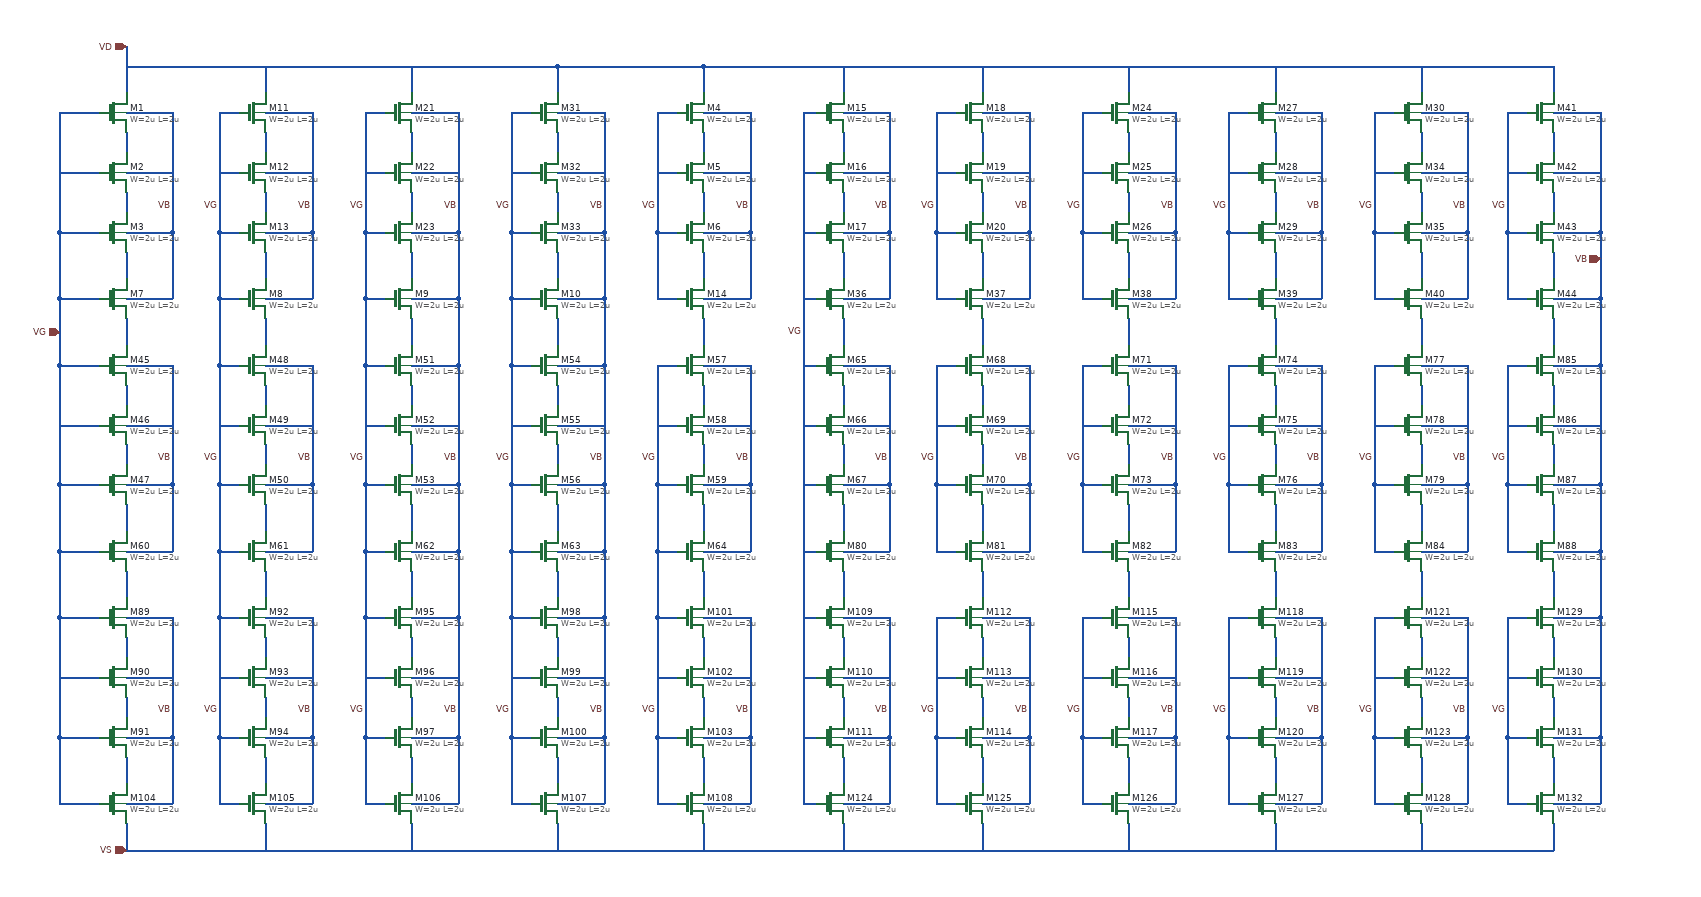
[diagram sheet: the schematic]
v {xschem version=3.4.0 file_version=1.2
}
G {}
K {}
V {}
S {}
E {}
N -420 -250 -420 -220 {
lab=#net1}
N -420 -160 -420 -130 {
lab=#net2}
N -420 -280 -350 -280 {
lab=VB}
N -420 -190 -350 -190 {
lab=VB}
N -420 -100 -350 -100 {
lab=VB}
N -520 -280 -460 -280 {
lab=#net3}
N -520 -100 -460 -100 {
lab=#net3}
N -520 -190 -460 -190 {
lab=#net3}
N -420 -380 -420 -310 {
lab=VD}
N -210 -280 -140 -280 {
lab=VB}
N -210 -190 -140 -190 {
lab=VB}
N -210 -100 -140 -100 {
lab=VB}
N 10 -280 80 -280 {
lab=VB}
N 10 -190 80 -190 {
lab=VB}
N 10 -100 80 -100 {
lab=VB}
N 230 -280 300 -280 {
lab=VB}
N 230 -190 300 -190 {
lab=VB}
N 230 -100 300 -100 {
lab=VB}
N -280 -280 -250 -280 {
lab=VG}
N -280 -100 -250 -100 {
lab=VG}
N -280 -190 -250 -190 {
lab=VG}
N -60 -280 -30 -280 {
lab=VG}
N -60 -100 -30 -100 {
lab=VG}
N -60 -190 -30 -190 {
lab=VG}
N 160 -280 190 -280 {
lab=VG}
N 160 -100 190 -100 {
lab=VG}
N 160 -190 190 -190 {
lab=VG}
N 230 -350 230 -310 {
lab=VD}
N 10 -350 10 -310 {
lab=VD}
N -210 -350 -210 -310 {
lab=VD}
N -420 -350 230 -350 {
lab=VD}
N -210 -250 -210 -220 {
lab=#net4}
N -210 -160 -210 -130 {
lab=#net5}
N 10 -250 10 -220 {
lab=#net6}
N 10 -160 10 -130 {
lab=#net7}
N 230 -250 230 -220 {
lab=#net8}
N 230 -160 230 -130 {
lab=#net9}
N -520 -280 -520 -100 {
lab=#net3}
N -350 -280 -350 -100 {
lab=VB}
N -280 -280 -280 -100 {
lab=VG}
N -140 -280 -140 -100 {
lab=VB}
N -60 -280 -60 -100 {
lab=VG}
N 80 -280 80 -100 {
lab=VB}
N 160 -280 160 -100 {
lab=VG}
N 300 -280 300 -100 {
lab=VB}
N -420 30 -420 70 {
lab=#net10}
N 230 30 230 70 {
lab=#net11}
N -210 30 -210 70 {
lab=#net12}
N 10 30 10 70 {
lab=#net13}
N 450 -280 520 -280 {
lab=VB}
N 450 -190 520 -190 {
lab=VB}
N 450 -100 520 -100 {
lab=VB}
N 380 -280 410 -280 {
lab=VG}
N 380 -100 410 -100 {
lab=VG}
N 380 -190 410 -190 {
lab=VG}
N 450 -250 450 -220 {
lab=#net14}
N 450 -160 450 -130 {
lab=#net15}
N 380 -280 380 -100 {
lab=VG}
N 520 -280 520 -100 {
lab=VB}
N 450 30 450 70 {
lab=#net16}
N 230 -350 450 -350 {
lab=VD}
N 450 -350 450 -340 {
lab=VD}
N 450 -340 450 -310 {
lab=VD}
N -420 -70 -420 -30 {
lab=#net17}
N -210 -70 -210 -30 {
lab=#net18}
N 10 -70 10 -30 {
lab=#net19}
N 230 -70 230 -30 {
lab=#net20}
N 450 -70 450 -30 {
lab=#net21}
N 380 -100 380 0 {
lab=VG}
N 380 0 410 0 {
lab=VG}
N 160 0 190 0 {
lab=VG}
N 160 -100 160 0 {
lab=VG}
N -50 0 -30 0 {
lab=VG}
N -60 0 -50 0 {
lab=VG}
N -60 -100 -60 0 {
lab=VG}
N -280 0 -250 0 {
lab=VG}
N -280 -100 -280 0 {
lab=VG}
N -520 0 -460 0 {
lab=#net3}
N -520 -100 -520 0 {
lab=#net3}
N -350 -100 -350 0 {
lab=VB}
N -420 0 -350 0 {
lab=VB}
N -140 -100 -140 0 {
lab=VB}
N -210 0 -140 0 {
lab=VB}
N 80 -100 80 0 {
lab=VB}
N 10 0 80 0 {
lab=VB}
N 300 -100 300 0 {
lab=VB}
N 230 0 300 0 {
lab=VB}
N 520 -100 520 0 {
lab=VB}
N 450 0 520 0 {
lab=VB}
N 660 -250 660 -220 {
lab=#net22}
N 660 -160 660 -130 {
lab=#net23}
N 660 -280 730 -280 {
lab=VB}
N 660 -190 730 -190 {
lab=VB}
N 660 -100 730 -100 {
lab=VB}
N 870 -280 940 -280 {
lab=VB}
N 870 -190 940 -190 {
lab=VB}
N 870 -100 940 -100 {
lab=VB}
N 1090 -280 1160 -280 {
lab=VB}
N 1090 -190 1160 -190 {
lab=VB}
N 1090 -100 1160 -100 {
lab=VB}
N 1310 -280 1380 -280 {
lab=VB}
N 1310 -190 1380 -190 {
lab=VB}
N 1310 -100 1380 -100 {
lab=VB}
N 800 -280 830 -280 {
lab=VG}
N 800 -100 830 -100 {
lab=VG}
N 800 -190 830 -190 {
lab=VG}
N 1020 -280 1050 -280 {
lab=VG}
N 1020 -100 1050 -100 {
lab=VG}
N 1020 -190 1050 -190 {
lab=VG}
N 1240 -280 1270 -280 {
lab=VG}
N 1240 -100 1270 -100 {
lab=VG}
N 1240 -190 1270 -190 {
lab=VG}
N 870 -250 870 -220 {
lab=#net24}
N 870 -160 870 -130 {
lab=#net25}
N 1090 -250 1090 -220 {
lab=#net26}
N 1090 -160 1090 -130 {
lab=#net27}
N 1310 -250 1310 -220 {
lab=#net28}
N 1310 -160 1310 -130 {
lab=#net29}
N 730 -280 730 -100 {
lab=VB}
N 800 -280 800 -100 {
lab=VG}
N 940 -280 940 -100 {
lab=VB}
N 1020 -280 1020 -100 {
lab=VG}
N 1160 -280 1160 -100 {
lab=VB}
N 1240 -280 1240 -100 {
lab=VG}
N 1380 -280 1380 -100 {
lab=VB}
N 660 30 660 70 {
lab=#net30}
N 1310 30 1310 70 {
lab=#net31}
N 870 30 870 70 {
lab=#net32}
N 1090 30 1090 70 {
lab=#net33}
N 1530 -280 1600 -280 {
lab=VB}
N 1530 -190 1600 -190 {
lab=VB}
N 1530 -100 1600 -100 {
lab=VB}
N 1460 -280 1490 -280 {
lab=VG}
N 1460 -100 1490 -100 {
lab=VG}
N 1460 -190 1490 -190 {
lab=VG}
N 1530 -250 1530 -220 {
lab=#net34}
N 1530 -160 1530 -130 {
lab=#net35}
N 1460 -280 1460 -100 {
lab=VG}
N 1600 -280 1600 -100 {
lab=VB}
N 1530 30 1530 70 {
lab=#net36}
N 660 -70 660 -30 {
lab=#net37}
N 870 -70 870 -30 {
lab=#net38}
N 1090 -70 1090 -30 {
lab=#net39}
N 1310 -70 1310 -30 {
lab=#net40}
N 1530 -70 1530 -30 {
lab=#net41}
N 1460 -100 1460 0 {
lab=VG}
N 1460 0 1490 0 {
lab=VG}
N 1240 0 1270 0 {
lab=VG}
N 1240 -100 1240 0 {
lab=VG}
N 1030 0 1050 0 {
lab=VG}
N 1020 0 1030 0 {
lab=VG}
N 1020 -100 1020 0 {
lab=VG}
N 800 0 830 0 {
lab=VG}
N 800 -100 800 0 {
lab=VG}
N 730 -100 730 0 {
lab=VB}
N 660 0 730 0 {
lab=VB}
N 940 -100 940 0 {
lab=VB}
N 870 0 940 0 {
lab=VB}
N 1160 -100 1160 0 {
lab=VB}
N 1090 0 1160 0 {
lab=VB}
N 1380 -100 1380 0 {
lab=VB}
N 1310 0 1380 0 {
lab=VB}
N 1600 -100 1600 0 {
lab=VB}
N 1530 0 1600 0 {
lab=VB}
N 1730 -280 1800 -280 {
lab=VB}
N 1730 -190 1800 -190 {
lab=VB}
N 1730 -100 1800 -100 {
lab=VB}
N 1660 -280 1690 -280 {
lab=VG}
N 1660 -100 1690 -100 {
lab=VG}
N 1660 -190 1690 -190 {
lab=VG}
N 1730 -250 1730 -220 {
lab=#net42}
N 1730 -160 1730 -130 {
lab=#net43}
N 1660 -280 1660 -100 {
lab=VG}
N 1800 -280 1800 -100 {
lab=VB}
N 1730 30 1730 70 {
lab=#net44}
N 1730 -70 1730 -30 {
lab=#net45}
N 1660 -100 1660 0 {
lab=VG}
N 1660 0 1690 0 {
lab=VG}
N 1800 -100 1800 0 {
lab=VB}
N 1730 0 1800 0 {
lab=VB}
N 450 -350 1730 -350 {
lab=VD}
N 1730 -350 1730 -310 {
lab=VD}
N 660 -350 660 -310 {
lab=VD}
N 870 -350 870 -310 {
lab=VD}
N 1090 -350 1090 -310 {
lab=VD}
N 1310 -350 1310 -310 {
lab=VD}
N 1530 -350 1530 -310 {
lab=VD}
N -420 130 -420 160 {
lab=#net1}
N -420 220 -420 250 {
lab=#net2}
N -420 100 -350 100 {
lab=VB}
N -420 190 -350 190 {
lab=VB}
N -420 280 -350 280 {
lab=VB}
N -520 100 -460 100 {
lab=#net3}
N -520 280 -460 280 {
lab=#net3}
N -520 190 -460 190 {
lab=#net3}
N -210 100 -140 100 {
lab=VB}
N -210 190 -140 190 {
lab=VB}
N -210 280 -140 280 {
lab=VB}
N 10 100 80 100 {
lab=VB}
N 10 190 80 190 {
lab=VB}
N 10 280 80 280 {
lab=VB}
N 230 100 300 100 {
lab=VB}
N 230 190 300 190 {
lab=VB}
N 230 280 300 280 {
lab=VB}
N -280 100 -250 100 {
lab=VG}
N -280 280 -250 280 {
lab=VG}
N -280 190 -250 190 {
lab=VG}
N -60 100 -30 100 {
lab=VG}
N -60 280 -30 280 {
lab=VG}
N -60 190 -30 190 {
lab=VG}
N 160 100 190 100 {
lab=VG}
N 160 280 190 280 {
lab=VG}
N 160 190 190 190 {
lab=VG}
N -210 130 -210 160 {
lab=#net4}
N -210 220 -210 250 {
lab=#net5}
N 10 130 10 160 {
lab=#net6}
N 10 220 10 250 {
lab=#net7}
N 230 130 230 160 {
lab=#net8}
N 230 220 230 250 {
lab=#net9}
N -520 100 -520 280 {
lab=#net3}
N -350 100 -350 280 {
lab=VB}
N -280 100 -280 280 {
lab=VG}
N -140 100 -140 280 {
lab=VB}
N -60 100 -60 280 {
lab=VG}
N 80 100 80 280 {
lab=VB}
N 160 100 160 280 {
lab=VG}
N 300 100 300 280 {
lab=VB}
N -420 410 -420 450 {
lab=#net10}
N 230 410 230 450 {
lab=#net11}
N -210 410 -210 450 {
lab=#net12}
N 10 410 10 450 {
lab=#net13}
N 450 100 520 100 {
lab=VB}
N 450 190 520 190 {
lab=VB}
N 450 280 520 280 {
lab=VB}
N 380 100 410 100 {
lab=VG}
N 380 280 410 280 {
lab=VG}
N 380 190 410 190 {
lab=VG}
N 450 130 450 160 {
lab=#net14}
N 450 220 450 250 {
lab=#net15}
N 380 100 380 280 {
lab=VG}
N 520 100 520 280 {
lab=VB}
N 450 410 450 450 {
lab=#net16}
N -420 310 -420 350 {
lab=#net17}
N -210 310 -210 350 {
lab=#net18}
N 10 310 10 350 {
lab=#net19}
N 230 310 230 350 {
lab=#net20}
N 450 310 450 350 {
lab=#net21}
N 380 280 380 380 {
lab=VG}
N 380 380 410 380 {
lab=VG}
N 160 380 190 380 {
lab=VG}
N 160 280 160 380 {
lab=VG}
N -50 380 -30 380 {
lab=VG}
N -60 380 -50 380 {
lab=VG}
N -60 280 -60 380 {
lab=VG}
N -280 380 -250 380 {
lab=VG}
N -280 280 -280 380 {
lab=VG}
N -520 380 -460 380 {
lab=#net3}
N -520 280 -520 380 {
lab=#net3}
N -350 280 -350 380 {
lab=VB}
N -420 380 -350 380 {
lab=VB}
N -140 280 -140 380 {
lab=VB}
N -210 380 -140 380 {
lab=VB}
N 80 280 80 380 {
lab=VB}
N 10 380 80 380 {
lab=VB}
N 300 280 300 380 {
lab=VB}
N 230 380 300 380 {
lab=VB}
N 520 280 520 380 {
lab=VB}
N 450 380 520 380 {
lab=VB}
N 660 130 660 160 {
lab=#net22}
N 660 220 660 250 {
lab=#net23}
N 660 100 730 100 {
lab=VB}
N 660 190 730 190 {
lab=VB}
N 660 280 730 280 {
lab=VB}
N 870 100 940 100 {
lab=VB}
N 870 190 940 190 {
lab=VB}
N 870 280 940 280 {
lab=VB}
N 1090 100 1160 100 {
lab=VB}
N 1090 190 1160 190 {
lab=VB}
N 1090 280 1160 280 {
lab=VB}
N 1310 100 1380 100 {
lab=VB}
N 1310 190 1380 190 {
lab=VB}
N 1310 280 1380 280 {
lab=VB}
N 800 100 830 100 {
lab=VG}
N 800 280 830 280 {
lab=VG}
N 800 190 830 190 {
lab=VG}
N 1020 100 1050 100 {
lab=VG}
N 1020 280 1050 280 {
lab=VG}
N 1020 190 1050 190 {
lab=VG}
N 1240 100 1270 100 {
lab=VG}
N 1240 280 1270 280 {
lab=VG}
N 1240 190 1270 190 {
lab=VG}
N 870 130 870 160 {
lab=#net24}
N 870 220 870 250 {
lab=#net25}
N 1090 130 1090 160 {
lab=#net26}
N 1090 220 1090 250 {
lab=#net27}
N 1310 130 1310 160 {
lab=#net28}
N 1310 220 1310 250 {
lab=#net29}
N 730 100 730 280 {
lab=VB}
N 800 100 800 280 {
lab=VG}
N 940 100 940 280 {
lab=VB}
N 1020 100 1020 280 {
lab=VG}
N 1160 100 1160 280 {
lab=VB}
N 1240 100 1240 280 {
lab=VG}
N 1380 100 1380 280 {
lab=VB}
N 660 410 660 450 {
lab=#net30}
N 1310 410 1310 450 {
lab=#net31}
N 870 410 870 450 {
lab=#net32}
N 1090 410 1090 450 {
lab=#net33}
N 1530 100 1600 100 {
lab=VB}
N 1530 190 1600 190 {
lab=VB}
N 1530 280 1600 280 {
lab=VB}
N 1460 100 1490 100 {
lab=VG}
N 1460 280 1490 280 {
lab=VG}
N 1460 190 1490 190 {
lab=VG}
N 1530 130 1530 160 {
lab=#net34}
N 1530 220 1530 250 {
lab=#net35}
N 1460 100 1460 280 {
lab=VG}
N 1600 100 1600 280 {
lab=VB}
N 1530 410 1530 450 {
lab=#net36}
N 660 310 660 350 {
lab=#net37}
N 870 310 870 350 {
lab=#net38}
N 1090 310 1090 350 {
lab=#net39}
N 1310 310 1310 350 {
lab=#net40}
N 1530 310 1530 350 {
lab=#net41}
N 1460 280 1460 380 {
lab=VG}
N 1460 380 1490 380 {
lab=VG}
N 1240 380 1270 380 {
lab=VG}
N 1240 280 1240 380 {
lab=VG}
N 1030 380 1050 380 {
lab=VG}
N 1020 380 1030 380 {
lab=VG}
N 1020 280 1020 380 {
lab=VG}
N 800 380 830 380 {
lab=VG}
N 800 280 800 380 {
lab=VG}
N 730 280 730 380 {
lab=VB}
N 660 380 730 380 {
lab=VB}
N 940 280 940 380 {
lab=VB}
N 870 380 940 380 {
lab=VB}
N 1160 280 1160 380 {
lab=VB}
N 1090 380 1160 380 {
lab=VB}
N 1380 280 1380 380 {
lab=VB}
N 1310 380 1380 380 {
lab=VB}
N 1600 280 1600 380 {
lab=VB}
N 1530 380 1600 380 {
lab=VB}
N 1730 100 1800 100 {
lab=VB}
N 1730 190 1800 190 {
lab=VB}
N 1730 280 1800 280 {
lab=VB}
N 1660 100 1690 100 {
lab=VG}
N 1660 280 1690 280 {
lab=VG}
N 1660 190 1690 190 {
lab=VG}
N 1730 130 1730 160 {
lab=#net42}
N 1730 220 1730 250 {
lab=#net43}
N 1660 100 1660 280 {
lab=VG}
N 1800 100 1800 280 {
lab=VB}
N 1730 410 1730 450 {
lab=#net44}
N 1730 310 1730 350 {
lab=#net45}
N 1660 280 1660 380 {
lab=VG}
N 1660 380 1690 380 {
lab=VG}
N 1800 280 1800 380 {
lab=VB}
N 1730 380 1800 380 {
lab=VB}
N -420 510 -420 540 {
lab=#net1}
N -420 600 -420 630 {
lab=#net2}
N -420 480 -350 480 {
lab=VB}
N -420 570 -350 570 {
lab=VB}
N -420 660 -350 660 {
lab=VB}
N -520 480 -460 480 {
lab=#net3}
N -520 660 -460 660 {
lab=#net3}
N -520 570 -460 570 {
lab=#net3}
N -210 480 -140 480 {
lab=VB}
N -210 570 -140 570 {
lab=VB}
N -210 660 -140 660 {
lab=VB}
N 10 480 80 480 {
lab=VB}
N 10 570 80 570 {
lab=VB}
N 10 660 80 660 {
lab=VB}
N 230 480 300 480 {
lab=VB}
N 230 570 300 570 {
lab=VB}
N 230 660 300 660 {
lab=VB}
N -280 480 -250 480 {
lab=VG}
N -280 660 -250 660 {
lab=VG}
N -280 570 -250 570 {
lab=VG}
N -60 480 -30 480 {
lab=VG}
N -60 660 -30 660 {
lab=VG}
N -60 570 -30 570 {
lab=VG}
N 160 480 190 480 {
lab=VG}
N 160 660 190 660 {
lab=VG}
N 160 570 190 570 {
lab=VG}
N -210 510 -210 540 {
lab=#net4}
N -210 600 -210 630 {
lab=#net5}
N 10 510 10 540 {
lab=#net6}
N 10 600 10 630 {
lab=#net7}
N 230 510 230 540 {
lab=#net8}
N 230 600 230 630 {
lab=#net9}
N -520 480 -520 660 {
lab=#net3}
N -350 480 -350 660 {
lab=VB}
N -280 480 -280 660 {
lab=VG}
N -140 480 -140 660 {
lab=VB}
N -60 480 -60 660 {
lab=VG}
N 80 480 80 660 {
lab=VB}
N 160 480 160 660 {
lab=VG}
N 300 480 300 660 {
lab=VB}
N -420 790 -420 830 {
lab=#net10}
N 230 790 230 830 {
lab=#net11}
N -210 790 -210 830 {
lab=#net12}
N 10 790 10 830 {
lab=#net13}
N 450 480 520 480 {
lab=VB}
N 450 570 520 570 {
lab=VB}
N 450 660 520 660 {
lab=VB}
N 380 480 410 480 {
lab=VG}
N 380 660 410 660 {
lab=VG}
N 380 570 410 570 {
lab=VG}
N 450 510 450 540 {
lab=#net14}
N 450 600 450 630 {
lab=#net15}
N 380 480 380 660 {
lab=VG}
N 520 480 520 660 {
lab=VB}
N 450 790 450 830 {
lab=#net16}
N -420 690 -420 730 {
lab=#net17}
N -210 690 -210 730 {
lab=#net18}
N 10 690 10 730 {
lab=#net19}
N 230 690 230 730 {
lab=#net20}
N 450 690 450 730 {
lab=#net21}
N 380 660 380 760 {
lab=VG}
N 380 760 410 760 {
lab=VG}
N 160 760 190 760 {
lab=VG}
N 160 660 160 760 {
lab=VG}
N -50 760 -30 760 {
lab=VG}
N -60 760 -50 760 {
lab=VG}
N -60 660 -60 760 {
lab=VG}
N -280 760 -250 760 {
lab=VG}
N -280 660 -280 760 {
lab=VG}
N -520 760 -460 760 {
lab=#net3}
N -520 660 -520 760 {
lab=#net3}
N -350 660 -350 760 {
lab=VB}
N -420 760 -350 760 {
lab=VB}
N -140 660 -140 760 {
lab=VB}
N -210 760 -140 760 {
lab=VB}
N 80 660 80 760 {
lab=VB}
N 10 760 80 760 {
lab=VB}
N 300 660 300 760 {
lab=VB}
N 230 760 300 760 {
lab=VB}
N 520 660 520 760 {
lab=VB}
N 450 760 520 760 {
lab=VB}
N 660 510 660 540 {
lab=#net22}
N 660 600 660 630 {
lab=#net23}
N 660 480 730 480 {
lab=VB}
N 660 570 730 570 {
lab=VB}
N 660 660 730 660 {
lab=VB}
N 870 480 940 480 {
lab=VB}
N 870 570 940 570 {
lab=VB}
N 870 660 940 660 {
lab=VB}
N 1090 480 1160 480 {
lab=VB}
N 1090 570 1160 570 {
lab=VB}
N 1090 660 1160 660 {
lab=VB}
N 1310 480 1380 480 {
lab=VB}
N 1310 570 1380 570 {
lab=VB}
N 1310 660 1380 660 {
lab=VB}
N 800 480 830 480 {
lab=VG}
N 800 660 830 660 {
lab=VG}
N 800 570 830 570 {
lab=VG}
N 1020 480 1050 480 {
lab=VG}
N 1020 660 1050 660 {
lab=VG}
N 1020 570 1050 570 {
lab=VG}
N 1240 480 1270 480 {
lab=VG}
N 1240 660 1270 660 {
lab=VG}
N 1240 570 1270 570 {
lab=VG}
N 870 510 870 540 {
lab=#net24}
N 870 600 870 630 {
lab=#net25}
N 1090 510 1090 540 {
lab=#net26}
N 1090 600 1090 630 {
lab=#net27}
N 1310 510 1310 540 {
lab=#net28}
N 1310 600 1310 630 {
lab=#net29}
N 730 480 730 660 {
lab=VB}
N 800 480 800 660 {
lab=VG}
N 940 480 940 660 {
lab=VB}
N 1020 480 1020 660 {
lab=VG}
N 1160 480 1160 660 {
lab=VB}
N 1240 480 1240 660 {
lab=VG}
N 1380 480 1380 660 {
lab=VB}
N 660 790 660 830 {
lab=#net30}
N 1310 790 1310 830 {
lab=#net31}
N 870 790 870 830 {
lab=#net32}
N 1090 790 1090 830 {
lab=#net33}
N 1530 480 1600 480 {
lab=VB}
N 1530 570 1600 570 {
lab=VB}
N 1530 660 1600 660 {
lab=VB}
N 1460 480 1490 480 {
lab=VG}
N 1460 660 1490 660 {
lab=VG}
N 1460 570 1490 570 {
lab=VG}
N 1530 510 1530 540 {
lab=#net34}
N 1530 600 1530 630 {
lab=#net35}
N 1460 480 1460 660 {
lab=VG}
N 1600 480 1600 660 {
lab=VB}
N 1530 790 1530 830 {
lab=#net36}
N 660 690 660 730 {
lab=#net37}
N 870 690 870 730 {
lab=#net38}
N 1090 690 1090 730 {
lab=#net39}
N 1310 690 1310 730 {
lab=#net40}
N 1530 690 1530 730 {
lab=#net41}
N 1460 660 1460 760 {
lab=VG}
N 1460 760 1490 760 {
lab=VG}
N 1240 760 1270 760 {
lab=VG}
N 1240 660 1240 760 {
lab=VG}
N 1030 760 1050 760 {
lab=VG}
N 1020 760 1030 760 {
lab=VG}
N 1020 660 1020 760 {
lab=VG}
N 800 760 830 760 {
lab=VG}
N 800 660 800 760 {
lab=VG}
N 730 660 730 760 {
lab=VB}
N 660 760 730 760 {
lab=VB}
N 940 660 940 760 {
lab=VB}
N 870 760 940 760 {
lab=VB}
N 1160 660 1160 760 {
lab=VB}
N 1090 760 1160 760 {
lab=VB}
N 1380 660 1380 760 {
lab=VB}
N 1310 760 1380 760 {
lab=VB}
N 1600 660 1600 760 {
lab=VB}
N 1530 760 1600 760 {
lab=VB}
N 1730 480 1800 480 {
lab=VB}
N 1730 570 1800 570 {
lab=VB}
N 1730 660 1800 660 {
lab=VB}
N 1660 480 1690 480 {
lab=VG}
N 1660 660 1690 660 {
lab=VG}
N 1660 570 1690 570 {
lab=VG}
N 1730 510 1730 540 {
lab=#net42}
N 1730 600 1730 630 {
lab=#net43}
N 1660 480 1660 660 {
lab=VG}
N 1800 480 1800 660 {
lab=VB}
N 1730 790 1730 830 {
lab=#net44}
N 1730 690 1730 730 {
lab=#net45}
N 1660 660 1660 760 {
lab=VG}
N 1660 760 1690 760 {
lab=VG}
N 1800 660 1800 760 {
lab=VB}
N 1730 760 1800 760 {
lab=VB}
N -520 0 -520 100 {}
N -520 380 -520 480 {}
N -280 -0 -280 100 {}
N -280 380 -280 480 {}
N -60 380 -60 480 {}
N -60 -0 -60 100 {}
N 160 0 160 100 {}
N 160 380 160 480 {}
N 80 0 80 100 {}
N 80 380 80 480 {}
N 300 0 300 100 {}
N 300 380 300 480 {}
N 380 380 380 480 {}
N 600 -280 620 -280 {}
N 600 -280 600 760 {}
N 600 760 620 760 {}
N 600 660 620 660 {}
N 600 570 620 570 {}
N 600 480 620 480 {}
N 600 380 620 380 {}
N 600 280 620 280 {}
N 600 190 620 190 {}
N 600 100 620 100 {}
N 600 -0 620 0 {}
N 600 -100 620 -100 {}
N 600 -190 620 -190 {}
N -420 830 1730 830 {}
N 1800 0 1800 100 {}
N 1800 380 1800 480 {}
C {devices/iopin.sym} -420 -380 3 0 {name=p1 lab=VD}
C {devices/iopin.sym} 1800 -60 0 0 {name=p2 lab=VB}
C {devices/iopin.sym} -520 50 2 0 {name=p3 lab=VG}
C {devices/iopin.sym} -420 830 1 0 {name=p4 lab=VS}
C {devices/lab_wire.sym} -280 -140 0 0 {name=p10 sig_type=std_logic lab=VG}
C {devices/lab_wire.sym} -60 -140 0 0 {name=p5 sig_type=std_logic lab=VG}
C {devices/lab_wire.sym} 160 -140 0 0 {name=p6 sig_type=std_logic lab=VG}
C {devices/lab_wire.sym} 300 -140 0 0 {name=p20 sig_type=std_logic lab=VB}
C {devices/lab_wire.sym} 80 -140 0 0 {name=p21 sig_type=std_logic lab=VB}
C {devices/lab_wire.sym} -140 -140 0 0 {name=p22 sig_type=std_logic lab=VB}
C {devices/lab_wire.sym} -350 -140 0 0 {name=p23 sig_type=std_logic lab=VB}
C {symbols/nfet_03v3.sym} -440 -280 0 0 {name=M1
L=2u
W=2u
nf=1
m=1
ad="'int((nf+1)/2) * W/nf * 0.18u'"
pd="'2*int((nf+1)/2) * (W/nf + 0.18u)'"
as="'int((nf+2)/2) * W/nf * 0.18u'"
ps="'2*int((nf+2)/2) * (W/nf + 0.18u)'"
nrd="'0.18u / W'" nrs="'0.18u / W'"
sa=0 sb=0 sd=0
model=nfet_03v3
spiceprefix=X
}
C {symbols/nfet_03v3.sym} -440 -190 0 0 {name=M2
L=2u
W=2u
nf=1
m=1
ad="'int((nf+1)/2) * W/nf * 0.18u'"
pd="'2*int((nf+1)/2) * (W/nf + 0.18u)'"
as="'int((nf+2)/2) * W/nf * 0.18u'"
ps="'2*int((nf+2)/2) * (W/nf + 0.18u)'"
nrd="'0.18u / W'" nrs="'0.18u / W'"
sa=0 sb=0 sd=0
model=nfet_03v3
spiceprefix=X
}
C {symbols/nfet_03v3.sym} -440 -100 0 0 {name=M3
L=2u
W=2u
nf=1
m=1
ad="'int((nf+1)/2) * W/nf * 0.18u'"
pd="'2*int((nf+1)/2) * (W/nf + 0.18u)'"
as="'int((nf+2)/2) * W/nf * 0.18u'"
ps="'2*int((nf+2)/2) * (W/nf + 0.18u)'"
nrd="'0.18u / W'" nrs="'0.18u / W'"
sa=0 sb=0 sd=0
model=nfet_03v3
spiceprefix=X
}
C {symbols/nfet_03v3.sym} -230 -280 0 0 {name=M11
L=2u
W=2u
nf=1
m=1
ad="'int((nf+1)/2) * W/nf * 0.18u'"
pd="'2*int((nf+1)/2) * (W/nf + 0.18u)'"
as="'int((nf+2)/2) * W/nf * 0.18u'"
ps="'2*int((nf+2)/2) * (W/nf + 0.18u)'"
nrd="'0.18u / W'" nrs="'0.18u / W'"
sa=0 sb=0 sd=0
model=nfet_03v3
spiceprefix=X
}
C {symbols/nfet_03v3.sym} -230 -190 0 0 {name=M12
L=2u
W=2u
nf=1
m=1
ad="'int((nf+1)/2) * W/nf * 0.18u'"
pd="'2*int((nf+1)/2) * (W/nf + 0.18u)'"
as="'int((nf+2)/2) * W/nf * 0.18u'"
ps="'2*int((nf+2)/2) * (W/nf + 0.18u)'"
nrd="'0.18u / W'" nrs="'0.18u / W'"
sa=0 sb=0 sd=0
model=nfet_03v3
spiceprefix=X
}
C {symbols/nfet_03v3.sym} -230 -100 0 0 {name=M13
L=2u
W=2u
nf=1
m=1
ad="'int((nf+1)/2) * W/nf * 0.18u'"
pd="'2*int((nf+1)/2) * (W/nf + 0.18u)'"
as="'int((nf+2)/2) * W/nf * 0.18u'"
ps="'2*int((nf+2)/2) * (W/nf + 0.18u)'"
nrd="'0.18u / W'" nrs="'0.18u / W'"
sa=0 sb=0 sd=0
model=nfet_03v3
spiceprefix=X
}
C {symbols/nfet_03v3.sym} -10 -280 0 0 {name=M21
L=2u
W=2u
nf=1
m=1
ad="'int((nf+1)/2) * W/nf * 0.18u'"
pd="'2*int((nf+1)/2) * (W/nf + 0.18u)'"
as="'int((nf+2)/2) * W/nf * 0.18u'"
ps="'2*int((nf+2)/2) * (W/nf + 0.18u)'"
nrd="'0.18u / W'" nrs="'0.18u / W'"
sa=0 sb=0 sd=0
model=nfet_03v3
spiceprefix=X
}
C {symbols/nfet_03v3.sym} -10 -190 0 0 {name=M22
L=2u
W=2u
nf=1
m=1
ad="'int((nf+1)/2) * W/nf * 0.18u'"
pd="'2*int((nf+1)/2) * (W/nf + 0.18u)'"
as="'int((nf+2)/2) * W/nf * 0.18u'"
ps="'2*int((nf+2)/2) * (W/nf + 0.18u)'"
nrd="'0.18u / W'" nrs="'0.18u / W'"
sa=0 sb=0 sd=0
model=nfet_03v3
spiceprefix=X
}
C {symbols/nfet_03v3.sym} -10 -100 0 0 {name=M23
L=2u
W=2u
nf=1
m=1
ad="'int((nf+1)/2) * W/nf * 0.18u'"
pd="'2*int((nf+1)/2) * (W/nf + 0.18u)'"
as="'int((nf+2)/2) * W/nf * 0.18u'"
ps="'2*int((nf+2)/2) * (W/nf + 0.18u)'"
nrd="'0.18u / W'" nrs="'0.18u / W'"
sa=0 sb=0 sd=0
model=nfet_03v3
spiceprefix=X
}
C {symbols/nfet_03v3.sym} 210 -280 0 0 {name=M31
L=2u
W=2u
nf=1
m=1
ad="'int((nf+1)/2) * W/nf * 0.18u'"
pd="'2*int((nf+1)/2) * (W/nf + 0.18u)'"
as="'int((nf+2)/2) * W/nf * 0.18u'"
ps="'2*int((nf+2)/2) * (W/nf + 0.18u)'"
nrd="'0.18u / W'" nrs="'0.18u / W'"
sa=0 sb=0 sd=0
model=nfet_03v3
spiceprefix=X
}
C {symbols/nfet_03v3.sym} 210 -190 0 0 {name=M32
L=2u
W=2u
nf=1
m=1
ad="'int((nf+1)/2) * W/nf * 0.18u'"
pd="'2*int((nf+1)/2) * (W/nf + 0.18u)'"
as="'int((nf+2)/2) * W/nf * 0.18u'"
ps="'2*int((nf+2)/2) * (W/nf + 0.18u)'"
nrd="'0.18u / W'" nrs="'0.18u / W'"
sa=0 sb=0 sd=0
model=nfet_03v3
spiceprefix=X
}
C {symbols/nfet_03v3.sym} 210 -100 0 0 {name=M33
L=2u
W=2u
nf=1
m=1
ad="'int((nf+1)/2) * W/nf * 0.18u'"
pd="'2*int((nf+1)/2) * (W/nf + 0.18u)'"
as="'int((nf+2)/2) * W/nf * 0.18u'"
ps="'2*int((nf+2)/2) * (W/nf + 0.18u)'"
nrd="'0.18u / W'" nrs="'0.18u / W'"
sa=0 sb=0 sd=0
model=nfet_03v3
spiceprefix=X
}
C {devices/lab_wire.sym} 380 -140 0 0 {name=p7 sig_type=std_logic lab=VG}
C {devices/lab_wire.sym} 520 -140 0 0 {name=p8 sig_type=std_logic lab=VB}
C {symbols/nfet_03v3.sym} 430 -280 0 0 {name=M4
L=2u
W=2u
nf=1
m=1
ad="'int((nf+1)/2) * W/nf * 0.18u'"
pd="'2*int((nf+1)/2) * (W/nf + 0.18u)'"
as="'int((nf+2)/2) * W/nf * 0.18u'"
ps="'2*int((nf+2)/2) * (W/nf + 0.18u)'"
nrd="'0.18u / W'" nrs="'0.18u / W'"
sa=0 sb=0 sd=0
model=nfet_03v3
spiceprefix=X
}
C {symbols/nfet_03v3.sym} 430 -190 0 0 {name=M5
L=2u
W=2u
nf=1
m=1
ad="'int((nf+1)/2) * W/nf * 0.18u'"
pd="'2*int((nf+1)/2) * (W/nf + 0.18u)'"
as="'int((nf+2)/2) * W/nf * 0.18u'"
ps="'2*int((nf+2)/2) * (W/nf + 0.18u)'"
nrd="'0.18u / W'" nrs="'0.18u / W'"
sa=0 sb=0 sd=0
model=nfet_03v3
spiceprefix=X
}
C {symbols/nfet_03v3.sym} 430 -100 0 0 {name=M6
L=2u
W=2u
nf=1
m=1
ad="'int((nf+1)/2) * W/nf * 0.18u'"
pd="'2*int((nf+1)/2) * (W/nf + 0.18u)'"
as="'int((nf+2)/2) * W/nf * 0.18u'"
ps="'2*int((nf+2)/2) * (W/nf + 0.18u)'"
nrd="'0.18u / W'" nrs="'0.18u / W'"
sa=0 sb=0 sd=0
model=nfet_03v3
spiceprefix=X
}
C {symbols/nfet_03v3.sym} -440 0 0 0 {name=M7
L=2u
W=2u
nf=1
m=1
ad="'int((nf+1)/2) * W/nf * 0.18u'"
pd="'2*int((nf+1)/2) * (W/nf + 0.18u)'"
as="'int((nf+2)/2) * W/nf * 0.18u'"
ps="'2*int((nf+2)/2) * (W/nf + 0.18u)'"
nrd="'0.18u / W'" nrs="'0.18u / W'"
sa=0 sb=0 sd=0
model=nfet_03v3
spiceprefix=X
}
C {symbols/nfet_03v3.sym} -230 0 0 0 {name=M8
L=2u
W=2u
nf=1
m=1
ad="'int((nf+1)/2) * W/nf * 0.18u'"
pd="'2*int((nf+1)/2) * (W/nf + 0.18u)'"
as="'int((nf+2)/2) * W/nf * 0.18u'"
ps="'2*int((nf+2)/2) * (W/nf + 0.18u)'"
nrd="'0.18u / W'" nrs="'0.18u / W'"
sa=0 sb=0 sd=0
model=nfet_03v3
spiceprefix=X
}
C {symbols/nfet_03v3.sym} -10 0 0 0 {name=M9
L=2u
W=2u
nf=1
m=1
ad="'int((nf+1)/2) * W/nf * 0.18u'"
pd="'2*int((nf+1)/2) * (W/nf + 0.18u)'"
as="'int((nf+2)/2) * W/nf * 0.18u'"
ps="'2*int((nf+2)/2) * (W/nf + 0.18u)'"
nrd="'0.18u / W'" nrs="'0.18u / W'"
sa=0 sb=0 sd=0
model=nfet_03v3
spiceprefix=X
}
C {symbols/nfet_03v3.sym} 210 0 0 0 {name=M10
L=2u
W=2u
nf=1
m=1
ad="'int((nf+1)/2) * W/nf * 0.18u'"
pd="'2*int((nf+1)/2) * (W/nf + 0.18u)'"
as="'int((nf+2)/2) * W/nf * 0.18u'"
ps="'2*int((nf+2)/2) * (W/nf + 0.18u)'"
nrd="'0.18u / W'" nrs="'0.18u / W'"
sa=0 sb=0 sd=0
model=nfet_03v3
spiceprefix=X
}
C {symbols/nfet_03v3.sym} 430 0 0 0 {name=M14
L=2u
W=2u
nf=1
m=1
ad="'int((nf+1)/2) * W/nf * 0.18u'"
pd="'2*int((nf+1)/2) * (W/nf + 0.18u)'"
as="'int((nf+2)/2) * W/nf * 0.18u'"
ps="'2*int((nf+2)/2) * (W/nf + 0.18u)'"
nrd="'0.18u / W'" nrs="'0.18u / W'"
sa=0 sb=0 sd=0
model=nfet_03v3
spiceprefix=X
}
C {devices/lab_wire.sym} 800 -140 0 0 {name=p9 sig_type=std_logic lab=VG}
C {devices/lab_wire.sym} 1020 -140 0 0 {name=p11 sig_type=std_logic lab=VG}
C {devices/lab_wire.sym} 1240 -140 0 0 {name=p12 sig_type=std_logic lab=VG}
C {devices/lab_wire.sym} 1380 -140 0 0 {name=p13 sig_type=std_logic lab=VB}
C {devices/lab_wire.sym} 1160 -140 0 0 {name=p14 sig_type=std_logic lab=VB}
C {devices/lab_wire.sym} 940 -140 0 0 {name=p15 sig_type=std_logic lab=VB}
C {devices/lab_wire.sym} 730 -140 0 0 {name=p16 sig_type=std_logic lab=VB}
C {symbols/nfet_03v3.sym} 640 -280 0 0 {name=M15
L=2u
W=2u
nf=1
m=1
ad="'int((nf+1)/2) * W/nf * 0.18u'"
pd="'2*int((nf+1)/2) * (W/nf + 0.18u)'"
as="'int((nf+2)/2) * W/nf * 0.18u'"
ps="'2*int((nf+2)/2) * (W/nf + 0.18u)'"
nrd="'0.18u / W'" nrs="'0.18u / W'"
sa=0 sb=0 sd=0
model=nfet_03v3
spiceprefix=X
}
C {symbols/nfet_03v3.sym} 640 -190 0 0 {name=M16
L=2u
W=2u
nf=1
m=1
ad="'int((nf+1)/2) * W/nf * 0.18u'"
pd="'2*int((nf+1)/2) * (W/nf + 0.18u)'"
as="'int((nf+2)/2) * W/nf * 0.18u'"
ps="'2*int((nf+2)/2) * (W/nf + 0.18u)'"
nrd="'0.18u / W'" nrs="'0.18u / W'"
sa=0 sb=0 sd=0
model=nfet_03v3
spiceprefix=X
}
C {symbols/nfet_03v3.sym} 640 -100 0 0 {name=M17
L=2u
W=2u
nf=1
m=1
ad="'int((nf+1)/2) * W/nf * 0.18u'"
pd="'2*int((nf+1)/2) * (W/nf + 0.18u)'"
as="'int((nf+2)/2) * W/nf * 0.18u'"
ps="'2*int((nf+2)/2) * (W/nf + 0.18u)'"
nrd="'0.18u / W'" nrs="'0.18u / W'"
sa=0 sb=0 sd=0
model=nfet_03v3
spiceprefix=X
}
C {symbols/nfet_03v3.sym} 850 -280 0 0 {name=M18
L=2u
W=2u
nf=1
m=1
ad="'int((nf+1)/2) * W/nf * 0.18u'"
pd="'2*int((nf+1)/2) * (W/nf + 0.18u)'"
as="'int((nf+2)/2) * W/nf * 0.18u'"
ps="'2*int((nf+2)/2) * (W/nf + 0.18u)'"
nrd="'0.18u / W'" nrs="'0.18u / W'"
sa=0 sb=0 sd=0
model=nfet_03v3
spiceprefix=X
}
C {symbols/nfet_03v3.sym} 850 -190 0 0 {name=M19
L=2u
W=2u
nf=1
m=1
ad="'int((nf+1)/2) * W/nf * 0.18u'"
pd="'2*int((nf+1)/2) * (W/nf + 0.18u)'"
as="'int((nf+2)/2) * W/nf * 0.18u'"
ps="'2*int((nf+2)/2) * (W/nf + 0.18u)'"
nrd="'0.18u / W'" nrs="'0.18u / W'"
sa=0 sb=0 sd=0
model=nfet_03v3
spiceprefix=X
}
C {symbols/nfet_03v3.sym} 850 -100 0 0 {name=M20
L=2u
W=2u
nf=1
m=1
ad="'int((nf+1)/2) * W/nf * 0.18u'"
pd="'2*int((nf+1)/2) * (W/nf + 0.18u)'"
as="'int((nf+2)/2) * W/nf * 0.18u'"
ps="'2*int((nf+2)/2) * (W/nf + 0.18u)'"
nrd="'0.18u / W'" nrs="'0.18u / W'"
sa=0 sb=0 sd=0
model=nfet_03v3
spiceprefix=X
}
C {symbols/nfet_03v3.sym} 1070 -280 0 0 {name=M24
L=2u
W=2u
nf=1
m=1
ad="'int((nf+1)/2) * W/nf * 0.18u'"
pd="'2*int((nf+1)/2) * (W/nf + 0.18u)'"
as="'int((nf+2)/2) * W/nf * 0.18u'"
ps="'2*int((nf+2)/2) * (W/nf + 0.18u)'"
nrd="'0.18u / W'" nrs="'0.18u / W'"
sa=0 sb=0 sd=0
model=nfet_03v3
spiceprefix=X
}
C {symbols/nfet_03v3.sym} 1070 -190 0 0 {name=M25
L=2u
W=2u
nf=1
m=1
ad="'int((nf+1)/2) * W/nf * 0.18u'"
pd="'2*int((nf+1)/2) * (W/nf + 0.18u)'"
as="'int((nf+2)/2) * W/nf * 0.18u'"
ps="'2*int((nf+2)/2) * (W/nf + 0.18u)'"
nrd="'0.18u / W'" nrs="'0.18u / W'"
sa=0 sb=0 sd=0
model=nfet_03v3
spiceprefix=X
}
C {symbols/nfet_03v3.sym} 1070 -100 0 0 {name=M26
L=2u
W=2u
nf=1
m=1
ad="'int((nf+1)/2) * W/nf * 0.18u'"
pd="'2*int((nf+1)/2) * (W/nf + 0.18u)'"
as="'int((nf+2)/2) * W/nf * 0.18u'"
ps="'2*int((nf+2)/2) * (W/nf + 0.18u)'"
nrd="'0.18u / W'" nrs="'0.18u / W'"
sa=0 sb=0 sd=0
model=nfet_03v3
spiceprefix=X
}
C {symbols/nfet_03v3.sym} 1290 -280 0 0 {name=M27
L=2u
W=2u
nf=1
m=1
ad="'int((nf+1)/2) * W/nf * 0.18u'"
pd="'2*int((nf+1)/2) * (W/nf + 0.18u)'"
as="'int((nf+2)/2) * W/nf * 0.18u'"
ps="'2*int((nf+2)/2) * (W/nf + 0.18u)'"
nrd="'0.18u / W'" nrs="'0.18u / W'"
sa=0 sb=0 sd=0
model=nfet_03v3
spiceprefix=X
}
C {symbols/nfet_03v3.sym} 1290 -190 0 0 {name=M28
L=2u
W=2u
nf=1
m=1
ad="'int((nf+1)/2) * W/nf * 0.18u'"
pd="'2*int((nf+1)/2) * (W/nf + 0.18u)'"
as="'int((nf+2)/2) * W/nf * 0.18u'"
ps="'2*int((nf+2)/2) * (W/nf + 0.18u)'"
nrd="'0.18u / W'" nrs="'0.18u / W'"
sa=0 sb=0 sd=0
model=nfet_03v3
spiceprefix=X
}
C {symbols/nfet_03v3.sym} 1290 -100 0 0 {name=M29
L=2u
W=2u
nf=1
m=1
ad="'int((nf+1)/2) * W/nf * 0.18u'"
pd="'2*int((nf+1)/2) * (W/nf + 0.18u)'"
as="'int((nf+2)/2) * W/nf * 0.18u'"
ps="'2*int((nf+2)/2) * (W/nf + 0.18u)'"
nrd="'0.18u / W'" nrs="'0.18u / W'"
sa=0 sb=0 sd=0
model=nfet_03v3
spiceprefix=X
}
C {devices/lab_wire.sym} 1460 -140 0 0 {name=p17 sig_type=std_logic lab=VG}
C {devices/lab_wire.sym} 1600 -140 0 0 {name=p18 sig_type=std_logic lab=VB}
C {symbols/nfet_03v3.sym} 1510 -280 0 0 {name=M30
L=2u
W=2u
nf=1
m=1
ad="'int((nf+1)/2) * W/nf * 0.18u'"
pd="'2*int((nf+1)/2) * (W/nf + 0.18u)'"
as="'int((nf+2)/2) * W/nf * 0.18u'"
ps="'2*int((nf+2)/2) * (W/nf + 0.18u)'"
nrd="'0.18u / W'" nrs="'0.18u / W'"
sa=0 sb=0 sd=0
model=nfet_03v3
spiceprefix=X
}
C {symbols/nfet_03v3.sym} 1510 -190 0 0 {name=M34
L=2u
W=2u
nf=1
m=1
ad="'int((nf+1)/2) * W/nf * 0.18u'"
pd="'2*int((nf+1)/2) * (W/nf + 0.18u)'"
as="'int((nf+2)/2) * W/nf * 0.18u'"
ps="'2*int((nf+2)/2) * (W/nf + 0.18u)'"
nrd="'0.18u / W'" nrs="'0.18u / W'"
sa=0 sb=0 sd=0
model=nfet_03v3
spiceprefix=X
}
C {symbols/nfet_03v3.sym} 1510 -100 0 0 {name=M35
L=2u
W=2u
nf=1
m=1
ad="'int((nf+1)/2) * W/nf * 0.18u'"
pd="'2*int((nf+1)/2) * (W/nf + 0.18u)'"
as="'int((nf+2)/2) * W/nf * 0.18u'"
ps="'2*int((nf+2)/2) * (W/nf + 0.18u)'"
nrd="'0.18u / W'" nrs="'0.18u / W'"
sa=0 sb=0 sd=0
model=nfet_03v3
spiceprefix=X
}
C {symbols/nfet_03v3.sym} 640 0 0 0 {name=M36
L=2u
W=2u
nf=1
m=1
ad="'int((nf+1)/2) * W/nf * 0.18u'"
pd="'2*int((nf+1)/2) * (W/nf + 0.18u)'"
as="'int((nf+2)/2) * W/nf * 0.18u'"
ps="'2*int((nf+2)/2) * (W/nf + 0.18u)'"
nrd="'0.18u / W'" nrs="'0.18u / W'"
sa=0 sb=0 sd=0
model=nfet_03v3
spiceprefix=X
}
C {symbols/nfet_03v3.sym} 850 0 0 0 {name=M37
L=2u
W=2u
nf=1
m=1
ad="'int((nf+1)/2) * W/nf * 0.18u'"
pd="'2*int((nf+1)/2) * (W/nf + 0.18u)'"
as="'int((nf+2)/2) * W/nf * 0.18u'"
ps="'2*int((nf+2)/2) * (W/nf + 0.18u)'"
nrd="'0.18u / W'" nrs="'0.18u / W'"
sa=0 sb=0 sd=0
model=nfet_03v3
spiceprefix=X
}
C {symbols/nfet_03v3.sym} 1070 0 0 0 {name=M38
L=2u
W=2u
nf=1
m=1
ad="'int((nf+1)/2) * W/nf * 0.18u'"
pd="'2*int((nf+1)/2) * (W/nf + 0.18u)'"
as="'int((nf+2)/2) * W/nf * 0.18u'"
ps="'2*int((nf+2)/2) * (W/nf + 0.18u)'"
nrd="'0.18u / W'" nrs="'0.18u / W'"
sa=0 sb=0 sd=0
model=nfet_03v3
spiceprefix=X
}
C {symbols/nfet_03v3.sym} 1290 0 0 0 {name=M39
L=2u
W=2u
nf=1
m=1
ad="'int((nf+1)/2) * W/nf * 0.18u'"
pd="'2*int((nf+1)/2) * (W/nf + 0.18u)'"
as="'int((nf+2)/2) * W/nf * 0.18u'"
ps="'2*int((nf+2)/2) * (W/nf + 0.18u)'"
nrd="'0.18u / W'" nrs="'0.18u / W'"
sa=0 sb=0 sd=0
model=nfet_03v3
spiceprefix=X
}
C {symbols/nfet_03v3.sym} 1510 0 0 0 {name=M40
L=2u
W=2u
nf=1
m=1
ad="'int((nf+1)/2) * W/nf * 0.18u'"
pd="'2*int((nf+1)/2) * (W/nf + 0.18u)'"
as="'int((nf+2)/2) * W/nf * 0.18u'"
ps="'2*int((nf+2)/2) * (W/nf + 0.18u)'"
nrd="'0.18u / W'" nrs="'0.18u / W'"
sa=0 sb=0 sd=0
model=nfet_03v3
spiceprefix=X
}
C {devices/lab_wire.sym} 1660 -140 0 0 {name=p19 sig_type=std_logic lab=VG}
C {symbols/nfet_03v3.sym} 1710 -280 0 0 {name=M41
L=2u
W=2u
nf=1
m=1
ad="'int((nf+1)/2) * W/nf * 0.18u'"
pd="'2*int((nf+1)/2) * (W/nf + 0.18u)'"
as="'int((nf+2)/2) * W/nf * 0.18u'"
ps="'2*int((nf+2)/2) * (W/nf + 0.18u)'"
nrd="'0.18u / W'" nrs="'0.18u / W'"
sa=0 sb=0 sd=0
model=nfet_03v3
spiceprefix=X
}
C {symbols/nfet_03v3.sym} 1710 -190 0 0 {name=M42
L=2u
W=2u
nf=1
m=1
ad="'int((nf+1)/2) * W/nf * 0.18u'"
pd="'2*int((nf+1)/2) * (W/nf + 0.18u)'"
as="'int((nf+2)/2) * W/nf * 0.18u'"
ps="'2*int((nf+2)/2) * (W/nf + 0.18u)'"
nrd="'0.18u / W'" nrs="'0.18u / W'"
sa=0 sb=0 sd=0
model=nfet_03v3
spiceprefix=X
}
C {symbols/nfet_03v3.sym} 1710 -100 0 0 {name=M43
L=2u
W=2u
nf=1
m=1
ad="'int((nf+1)/2) * W/nf * 0.18u'"
pd="'2*int((nf+1)/2) * (W/nf + 0.18u)'"
as="'int((nf+2)/2) * W/nf * 0.18u'"
ps="'2*int((nf+2)/2) * (W/nf + 0.18u)'"
nrd="'0.18u / W'" nrs="'0.18u / W'"
sa=0 sb=0 sd=0
model=nfet_03v3
spiceprefix=X
}
C {symbols/nfet_03v3.sym} 1710 0 0 0 {name=M44
L=2u
W=2u
nf=1
m=1
ad="'int((nf+1)/2) * W/nf * 0.18u'"
pd="'2*int((nf+1)/2) * (W/nf + 0.18u)'"
as="'int((nf+2)/2) * W/nf * 0.18u'"
ps="'2*int((nf+2)/2) * (W/nf + 0.18u)'"
nrd="'0.18u / W'" nrs="'0.18u / W'"
sa=0 sb=0 sd=0
model=nfet_03v3
spiceprefix=X
}
C {devices/lab_wire.sym} -280 240 0 0 {name=p24 sig_type=std_logic lab=VG}
C {devices/lab_wire.sym} -60 240 0 0 {name=p25 sig_type=std_logic lab=VG}
C {devices/lab_wire.sym} 160 240 0 0 {name=p26 sig_type=std_logic lab=VG}
C {devices/lab_wire.sym} 300 240 0 0 {name=p27 sig_type=std_logic lab=VB}
C {devices/lab_wire.sym} 80 240 0 0 {name=p28 sig_type=std_logic lab=VB}
C {devices/lab_wire.sym} -140 240 0 0 {name=p29 sig_type=std_logic lab=VB}
C {devices/lab_wire.sym} -350 240 0 0 {name=p30 sig_type=std_logic lab=VB}
C {symbols/nfet_03v3.sym} -440 100 0 0 {name=M45
L=2u
W=2u
nf=1
m=1
ad="'int((nf+1)/2) * W/nf * 0.18u'"
pd="'2*int((nf+1)/2) * (W/nf + 0.18u)'"
as="'int((nf+2)/2) * W/nf * 0.18u'"
ps="'2*int((nf+2)/2) * (W/nf + 0.18u)'"
nrd="'0.18u / W'" nrs="'0.18u / W'"
sa=0 sb=0 sd=0
model=nfet_03v3
spiceprefix=X
}
C {symbols/nfet_03v3.sym} -440 190 0 0 {name=M46
L=2u
W=2u
nf=1
m=1
ad="'int((nf+1)/2) * W/nf * 0.18u'"
pd="'2*int((nf+1)/2) * (W/nf + 0.18u)'"
as="'int((nf+2)/2) * W/nf * 0.18u'"
ps="'2*int((nf+2)/2) * (W/nf + 0.18u)'"
nrd="'0.18u / W'" nrs="'0.18u / W'"
sa=0 sb=0 sd=0
model=nfet_03v3
spiceprefix=X
}
C {symbols/nfet_03v3.sym} -440 280 0 0 {name=M47
L=2u
W=2u
nf=1
m=1
ad="'int((nf+1)/2) * W/nf * 0.18u'"
pd="'2*int((nf+1)/2) * (W/nf + 0.18u)'"
as="'int((nf+2)/2) * W/nf * 0.18u'"
ps="'2*int((nf+2)/2) * (W/nf + 0.18u)'"
nrd="'0.18u / W'" nrs="'0.18u / W'"
sa=0 sb=0 sd=0
model=nfet_03v3
spiceprefix=X
}
C {symbols/nfet_03v3.sym} -230 100 0 0 {name=M48
L=2u
W=2u
nf=1
m=1
ad="'int((nf+1)/2) * W/nf * 0.18u'"
pd="'2*int((nf+1)/2) * (W/nf + 0.18u)'"
as="'int((nf+2)/2) * W/nf * 0.18u'"
ps="'2*int((nf+2)/2) * (W/nf + 0.18u)'"
nrd="'0.18u / W'" nrs="'0.18u / W'"
sa=0 sb=0 sd=0
model=nfet_03v3
spiceprefix=X
}
C {symbols/nfet_03v3.sym} -230 190 0 0 {name=M49
L=2u
W=2u
nf=1
m=1
ad="'int((nf+1)/2) * W/nf * 0.18u'"
pd="'2*int((nf+1)/2) * (W/nf + 0.18u)'"
as="'int((nf+2)/2) * W/nf * 0.18u'"
ps="'2*int((nf+2)/2) * (W/nf + 0.18u)'"
nrd="'0.18u / W'" nrs="'0.18u / W'"
sa=0 sb=0 sd=0
model=nfet_03v3
spiceprefix=X
}
C {symbols/nfet_03v3.sym} -230 280 0 0 {name=M50
L=2u
W=2u
nf=1
m=1
ad="'int((nf+1)/2) * W/nf * 0.18u'"
pd="'2*int((nf+1)/2) * (W/nf + 0.18u)'"
as="'int((nf+2)/2) * W/nf * 0.18u'"
ps="'2*int((nf+2)/2) * (W/nf + 0.18u)'"
nrd="'0.18u / W'" nrs="'0.18u / W'"
sa=0 sb=0 sd=0
model=nfet_03v3
spiceprefix=X
}
C {symbols/nfet_03v3.sym} -10 100 0 0 {name=M51
L=2u
W=2u
nf=1
m=1
ad="'int((nf+1)/2) * W/nf * 0.18u'"
pd="'2*int((nf+1)/2) * (W/nf + 0.18u)'"
as="'int((nf+2)/2) * W/nf * 0.18u'"
ps="'2*int((nf+2)/2) * (W/nf + 0.18u)'"
nrd="'0.18u / W'" nrs="'0.18u / W'"
sa=0 sb=0 sd=0
model=nfet_03v3
spiceprefix=X
}
C {symbols/nfet_03v3.sym} -10 190 0 0 {name=M52
L=2u
W=2u
nf=1
m=1
ad="'int((nf+1)/2) * W/nf * 0.18u'"
pd="'2*int((nf+1)/2) * (W/nf + 0.18u)'"
as="'int((nf+2)/2) * W/nf * 0.18u'"
ps="'2*int((nf+2)/2) * (W/nf + 0.18u)'"
nrd="'0.18u / W'" nrs="'0.18u / W'"
sa=0 sb=0 sd=0
model=nfet_03v3
spiceprefix=X
}
C {symbols/nfet_03v3.sym} -10 280 0 0 {name=M53
L=2u
W=2u
nf=1
m=1
ad="'int((nf+1)/2) * W/nf * 0.18u'"
pd="'2*int((nf+1)/2) * (W/nf + 0.18u)'"
as="'int((nf+2)/2) * W/nf * 0.18u'"
ps="'2*int((nf+2)/2) * (W/nf + 0.18u)'"
nrd="'0.18u / W'" nrs="'0.18u / W'"
sa=0 sb=0 sd=0
model=nfet_03v3
spiceprefix=X
}
C {symbols/nfet_03v3.sym} 210 100 0 0 {name=M54
L=2u
W=2u
nf=1
m=1
ad="'int((nf+1)/2) * W/nf * 0.18u'"
pd="'2*int((nf+1)/2) * (W/nf + 0.18u)'"
as="'int((nf+2)/2) * W/nf * 0.18u'"
ps="'2*int((nf+2)/2) * (W/nf + 0.18u)'"
nrd="'0.18u / W'" nrs="'0.18u / W'"
sa=0 sb=0 sd=0
model=nfet_03v3
spiceprefix=X
}
C {symbols/nfet_03v3.sym} 210 190 0 0 {name=M55
L=2u
W=2u
nf=1
m=1
ad="'int((nf+1)/2) * W/nf * 0.18u'"
pd="'2*int((nf+1)/2) * (W/nf + 0.18u)'"
as="'int((nf+2)/2) * W/nf * 0.18u'"
ps="'2*int((nf+2)/2) * (W/nf + 0.18u)'"
nrd="'0.18u / W'" nrs="'0.18u / W'"
sa=0 sb=0 sd=0
model=nfet_03v3
spiceprefix=X
}
C {symbols/nfet_03v3.sym} 210 280 0 0 {name=M56
L=2u
W=2u
nf=1
m=1
ad="'int((nf+1)/2) * W/nf * 0.18u'"
pd="'2*int((nf+1)/2) * (W/nf + 0.18u)'"
as="'int((nf+2)/2) * W/nf * 0.18u'"
ps="'2*int((nf+2)/2) * (W/nf + 0.18u)'"
nrd="'0.18u / W'" nrs="'0.18u / W'"
sa=0 sb=0 sd=0
model=nfet_03v3
spiceprefix=X
}
C {devices/lab_wire.sym} 380 240 0 0 {name=p31 sig_type=std_logic lab=VG}
C {devices/lab_wire.sym} 520 240 0 0 {name=p32 sig_type=std_logic lab=VB}
C {symbols/nfet_03v3.sym} 430 100 0 0 {name=M57
L=2u
W=2u
nf=1
m=1
ad="'int((nf+1)/2) * W/nf * 0.18u'"
pd="'2*int((nf+1)/2) * (W/nf + 0.18u)'"
as="'int((nf+2)/2) * W/nf * 0.18u'"
ps="'2*int((nf+2)/2) * (W/nf + 0.18u)'"
nrd="'0.18u / W'" nrs="'0.18u / W'"
sa=0 sb=0 sd=0
model=nfet_03v3
spiceprefix=X
}
C {symbols/nfet_03v3.sym} 430 190 0 0 {name=M58
L=2u
W=2u
nf=1
m=1
ad="'int((nf+1)/2) * W/nf * 0.18u'"
pd="'2*int((nf+1)/2) * (W/nf + 0.18u)'"
as="'int((nf+2)/2) * W/nf * 0.18u'"
ps="'2*int((nf+2)/2) * (W/nf + 0.18u)'"
nrd="'0.18u / W'" nrs="'0.18u / W'"
sa=0 sb=0 sd=0
model=nfet_03v3
spiceprefix=X
}
C {symbols/nfet_03v3.sym} 430 280 0 0 {name=M59
L=2u
W=2u
nf=1
m=1
ad="'int((nf+1)/2) * W/nf * 0.18u'"
pd="'2*int((nf+1)/2) * (W/nf + 0.18u)'"
as="'int((nf+2)/2) * W/nf * 0.18u'"
ps="'2*int((nf+2)/2) * (W/nf + 0.18u)'"
nrd="'0.18u / W'" nrs="'0.18u / W'"
sa=0 sb=0 sd=0
model=nfet_03v3
spiceprefix=X
}
C {symbols/nfet_03v3.sym} -440 380 0 0 {name=M60
L=2u
W=2u
nf=1
m=1
ad="'int((nf+1)/2) * W/nf * 0.18u'"
pd="'2*int((nf+1)/2) * (W/nf + 0.18u)'"
as="'int((nf+2)/2) * W/nf * 0.18u'"
ps="'2*int((nf+2)/2) * (W/nf + 0.18u)'"
nrd="'0.18u / W'" nrs="'0.18u / W'"
sa=0 sb=0 sd=0
model=nfet_03v3
spiceprefix=X
}
C {symbols/nfet_03v3.sym} -230 380 0 0 {name=M61
L=2u
W=2u
nf=1
m=1
ad="'int((nf+1)/2) * W/nf * 0.18u'"
pd="'2*int((nf+1)/2) * (W/nf + 0.18u)'"
as="'int((nf+2)/2) * W/nf * 0.18u'"
ps="'2*int((nf+2)/2) * (W/nf + 0.18u)'"
nrd="'0.18u / W'" nrs="'0.18u / W'"
sa=0 sb=0 sd=0
model=nfet_03v3
spiceprefix=X
}
C {symbols/nfet_03v3.sym} -10 380 0 0 {name=M62
L=2u
W=2u
nf=1
m=1
ad="'int((nf+1)/2) * W/nf * 0.18u'"
pd="'2*int((nf+1)/2) * (W/nf + 0.18u)'"
as="'int((nf+2)/2) * W/nf * 0.18u'"
ps="'2*int((nf+2)/2) * (W/nf + 0.18u)'"
nrd="'0.18u / W'" nrs="'0.18u / W'"
sa=0 sb=0 sd=0
model=nfet_03v3
spiceprefix=X
}
C {symbols/nfet_03v3.sym} 210 380 0 0 {name=M63
L=2u
W=2u
nf=1
m=1
ad="'int((nf+1)/2) * W/nf * 0.18u'"
pd="'2*int((nf+1)/2) * (W/nf + 0.18u)'"
as="'int((nf+2)/2) * W/nf * 0.18u'"
ps="'2*int((nf+2)/2) * (W/nf + 0.18u)'"
nrd="'0.18u / W'" nrs="'0.18u / W'"
sa=0 sb=0 sd=0
model=nfet_03v3
spiceprefix=X
}
C {symbols/nfet_03v3.sym} 430 380 0 0 {name=M64
L=2u
W=2u
nf=1
m=1
ad="'int((nf+1)/2) * W/nf * 0.18u'"
pd="'2*int((nf+1)/2) * (W/nf + 0.18u)'"
as="'int((nf+2)/2) * W/nf * 0.18u'"
ps="'2*int((nf+2)/2) * (W/nf + 0.18u)'"
nrd="'0.18u / W'" nrs="'0.18u / W'"
sa=0 sb=0 sd=0
model=nfet_03v3
spiceprefix=X
}
C {devices/lab_wire.sym} 800 240 0 0 {name=p33 sig_type=std_logic lab=VG}
C {devices/lab_wire.sym} 1020 240 0 0 {name=p34 sig_type=std_logic lab=VG}
C {devices/lab_wire.sym} 1240 240 0 0 {name=p35 sig_type=std_logic lab=VG}
C {devices/lab_wire.sym} 1380 240 0 0 {name=p36 sig_type=std_logic lab=VB}
C {devices/lab_wire.sym} 1160 240 0 0 {name=p37 sig_type=std_logic lab=VB}
C {devices/lab_wire.sym} 940 240 0 0 {name=p38 sig_type=std_logic lab=VB}
C {devices/lab_wire.sym} 730 240 0 0 {name=p39 sig_type=std_logic lab=VB}
C {symbols/nfet_03v3.sym} 640 100 0 0 {name=M65
L=2u
W=2u
nf=1
m=1
ad="'int((nf+1)/2) * W/nf * 0.18u'"
pd="'2*int((nf+1)/2) * (W/nf + 0.18u)'"
as="'int((nf+2)/2) * W/nf * 0.18u'"
ps="'2*int((nf+2)/2) * (W/nf + 0.18u)'"
nrd="'0.18u / W'" nrs="'0.18u / W'"
sa=0 sb=0 sd=0
model=nfet_03v3
spiceprefix=X
}
C {symbols/nfet_03v3.sym} 640 190 0 0 {name=M66
L=2u
W=2u
nf=1
m=1
ad="'int((nf+1)/2) * W/nf * 0.18u'"
pd="'2*int((nf+1)/2) * (W/nf + 0.18u)'"
as="'int((nf+2)/2) * W/nf * 0.18u'"
ps="'2*int((nf+2)/2) * (W/nf + 0.18u)'"
nrd="'0.18u / W'" nrs="'0.18u / W'"
sa=0 sb=0 sd=0
model=nfet_03v3
spiceprefix=X
}
C {symbols/nfet_03v3.sym} 640 280 0 0 {name=M67
L=2u
W=2u
nf=1
m=1
ad="'int((nf+1)/2) * W/nf * 0.18u'"
pd="'2*int((nf+1)/2) * (W/nf + 0.18u)'"
as="'int((nf+2)/2) * W/nf * 0.18u'"
ps="'2*int((nf+2)/2) * (W/nf + 0.18u)'"
nrd="'0.18u / W'" nrs="'0.18u / W'"
sa=0 sb=0 sd=0
model=nfet_03v3
spiceprefix=X
}
C {symbols/nfet_03v3.sym} 850 100 0 0 {name=M68
L=2u
W=2u
nf=1
m=1
ad="'int((nf+1)/2) * W/nf * 0.18u'"
pd="'2*int((nf+1)/2) * (W/nf + 0.18u)'"
as="'int((nf+2)/2) * W/nf * 0.18u'"
ps="'2*int((nf+2)/2) * (W/nf + 0.18u)'"
nrd="'0.18u / W'" nrs="'0.18u / W'"
sa=0 sb=0 sd=0
model=nfet_03v3
spiceprefix=X
}
C {symbols/nfet_03v3.sym} 850 190 0 0 {name=M69
L=2u
W=2u
nf=1
m=1
ad="'int((nf+1)/2) * W/nf * 0.18u'"
pd="'2*int((nf+1)/2) * (W/nf + 0.18u)'"
as="'int((nf+2)/2) * W/nf * 0.18u'"
ps="'2*int((nf+2)/2) * (W/nf + 0.18u)'"
nrd="'0.18u / W'" nrs="'0.18u / W'"
sa=0 sb=0 sd=0
model=nfet_03v3
spiceprefix=X
}
C {symbols/nfet_03v3.sym} 850 280 0 0 {name=M70
L=2u
W=2u
nf=1
m=1
ad="'int((nf+1)/2) * W/nf * 0.18u'"
pd="'2*int((nf+1)/2) * (W/nf + 0.18u)'"
as="'int((nf+2)/2) * W/nf * 0.18u'"
ps="'2*int((nf+2)/2) * (W/nf + 0.18u)'"
nrd="'0.18u / W'" nrs="'0.18u / W'"
sa=0 sb=0 sd=0
model=nfet_03v3
spiceprefix=X
}
C {symbols/nfet_03v3.sym} 1070 100 0 0 {name=M71
L=2u
W=2u
nf=1
m=1
ad="'int((nf+1)/2) * W/nf * 0.18u'"
pd="'2*int((nf+1)/2) * (W/nf + 0.18u)'"
as="'int((nf+2)/2) * W/nf * 0.18u'"
ps="'2*int((nf+2)/2) * (W/nf + 0.18u)'"
nrd="'0.18u / W'" nrs="'0.18u / W'"
sa=0 sb=0 sd=0
model=nfet_03v3
spiceprefix=X
}
C {symbols/nfet_03v3.sym} 1070 190 0 0 {name=M72
L=2u
W=2u
nf=1
m=1
ad="'int((nf+1)/2) * W/nf * 0.18u'"
pd="'2*int((nf+1)/2) * (W/nf + 0.18u)'"
as="'int((nf+2)/2) * W/nf * 0.18u'"
ps="'2*int((nf+2)/2) * (W/nf + 0.18u)'"
nrd="'0.18u / W'" nrs="'0.18u / W'"
sa=0 sb=0 sd=0
model=nfet_03v3
spiceprefix=X
}
C {symbols/nfet_03v3.sym} 1070 280 0 0 {name=M73
L=2u
W=2u
nf=1
m=1
ad="'int((nf+1)/2) * W/nf * 0.18u'"
pd="'2*int((nf+1)/2) * (W/nf + 0.18u)'"
as="'int((nf+2)/2) * W/nf * 0.18u'"
ps="'2*int((nf+2)/2) * (W/nf + 0.18u)'"
nrd="'0.18u / W'" nrs="'0.18u / W'"
sa=0 sb=0 sd=0
model=nfet_03v3
spiceprefix=X
}
C {symbols/nfet_03v3.sym} 1290 100 0 0 {name=M74
L=2u
W=2u
nf=1
m=1
ad="'int((nf+1)/2) * W/nf * 0.18u'"
pd="'2*int((nf+1)/2) * (W/nf + 0.18u)'"
as="'int((nf+2)/2) * W/nf * 0.18u'"
ps="'2*int((nf+2)/2) * (W/nf + 0.18u)'"
nrd="'0.18u / W'" nrs="'0.18u / W'"
sa=0 sb=0 sd=0
model=nfet_03v3
spiceprefix=X
}
C {symbols/nfet_03v3.sym} 1290 190 0 0 {name=M75
L=2u
W=2u
nf=1
m=1
ad="'int((nf+1)/2) * W/nf * 0.18u'"
pd="'2*int((nf+1)/2) * (W/nf + 0.18u)'"
as="'int((nf+2)/2) * W/nf * 0.18u'"
ps="'2*int((nf+2)/2) * (W/nf + 0.18u)'"
nrd="'0.18u / W'" nrs="'0.18u / W'"
sa=0 sb=0 sd=0
model=nfet_03v3
spiceprefix=X
}
C {symbols/nfet_03v3.sym} 1290 280 0 0 {name=M76
L=2u
W=2u
nf=1
m=1
ad="'int((nf+1)/2) * W/nf * 0.18u'"
pd="'2*int((nf+1)/2) * (W/nf + 0.18u)'"
as="'int((nf+2)/2) * W/nf * 0.18u'"
ps="'2*int((nf+2)/2) * (W/nf + 0.18u)'"
nrd="'0.18u / W'" nrs="'0.18u / W'"
sa=0 sb=0 sd=0
model=nfet_03v3
spiceprefix=X
}
C {devices/lab_wire.sym} 1460 240 0 0 {name=p40 sig_type=std_logic lab=VG}
C {devices/lab_wire.sym} 1600 240 0 0 {name=p41 sig_type=std_logic lab=VB}
C {symbols/nfet_03v3.sym} 1510 100 0 0 {name=M77
L=2u
W=2u
nf=1
m=1
ad="'int((nf+1)/2) * W/nf * 0.18u'"
pd="'2*int((nf+1)/2) * (W/nf + 0.18u)'"
as="'int((nf+2)/2) * W/nf * 0.18u'"
ps="'2*int((nf+2)/2) * (W/nf + 0.18u)'"
nrd="'0.18u / W'" nrs="'0.18u / W'"
sa=0 sb=0 sd=0
model=nfet_03v3
spiceprefix=X
}
C {symbols/nfet_03v3.sym} 1510 190 0 0 {name=M78
L=2u
W=2u
nf=1
m=1
ad="'int((nf+1)/2) * W/nf * 0.18u'"
pd="'2*int((nf+1)/2) * (W/nf + 0.18u)'"
as="'int((nf+2)/2) * W/nf * 0.18u'"
ps="'2*int((nf+2)/2) * (W/nf + 0.18u)'"
nrd="'0.18u / W'" nrs="'0.18u / W'"
sa=0 sb=0 sd=0
model=nfet_03v3
spiceprefix=X
}
C {symbols/nfet_03v3.sym} 1510 280 0 0 {name=M79
L=2u
W=2u
nf=1
m=1
ad="'int((nf+1)/2) * W/nf * 0.18u'"
pd="'2*int((nf+1)/2) * (W/nf + 0.18u)'"
as="'int((nf+2)/2) * W/nf * 0.18u'"
ps="'2*int((nf+2)/2) * (W/nf + 0.18u)'"
nrd="'0.18u / W'" nrs="'0.18u / W'"
sa=0 sb=0 sd=0
model=nfet_03v3
spiceprefix=X
}
C {symbols/nfet_03v3.sym} 640 380 0 0 {name=M80
L=2u
W=2u
nf=1
m=1
ad="'int((nf+1)/2) * W/nf * 0.18u'"
pd="'2*int((nf+1)/2) * (W/nf + 0.18u)'"
as="'int((nf+2)/2) * W/nf * 0.18u'"
ps="'2*int((nf+2)/2) * (W/nf + 0.18u)'"
nrd="'0.18u / W'" nrs="'0.18u / W'"
sa=0 sb=0 sd=0
model=nfet_03v3
spiceprefix=X
}
C {symbols/nfet_03v3.sym} 850 380 0 0 {name=M81
L=2u
W=2u
nf=1
m=1
ad="'int((nf+1)/2) * W/nf * 0.18u'"
pd="'2*int((nf+1)/2) * (W/nf + 0.18u)'"
as="'int((nf+2)/2) * W/nf * 0.18u'"
ps="'2*int((nf+2)/2) * (W/nf + 0.18u)'"
nrd="'0.18u / W'" nrs="'0.18u / W'"
sa=0 sb=0 sd=0
model=nfet_03v3
spiceprefix=X
}
C {symbols/nfet_03v3.sym} 1070 380 0 0 {name=M82
L=2u
W=2u
nf=1
m=1
ad="'int((nf+1)/2) * W/nf * 0.18u'"
pd="'2*int((nf+1)/2) * (W/nf + 0.18u)'"
as="'int((nf+2)/2) * W/nf * 0.18u'"
ps="'2*int((nf+2)/2) * (W/nf + 0.18u)'"
nrd="'0.18u / W'" nrs="'0.18u / W'"
sa=0 sb=0 sd=0
model=nfet_03v3
spiceprefix=X
}
C {symbols/nfet_03v3.sym} 1290 380 0 0 {name=M83
L=2u
W=2u
nf=1
m=1
ad="'int((nf+1)/2) * W/nf * 0.18u'"
pd="'2*int((nf+1)/2) * (W/nf + 0.18u)'"
as="'int((nf+2)/2) * W/nf * 0.18u'"
ps="'2*int((nf+2)/2) * (W/nf + 0.18u)'"
nrd="'0.18u / W'" nrs="'0.18u / W'"
sa=0 sb=0 sd=0
model=nfet_03v3
spiceprefix=X
}
C {symbols/nfet_03v3.sym} 1510 380 0 0 {name=M84
L=2u
W=2u
nf=1
m=1
ad="'int((nf+1)/2) * W/nf * 0.18u'"
pd="'2*int((nf+1)/2) * (W/nf + 0.18u)'"
as="'int((nf+2)/2) * W/nf * 0.18u'"
ps="'2*int((nf+2)/2) * (W/nf + 0.18u)'"
nrd="'0.18u / W'" nrs="'0.18u / W'"
sa=0 sb=0 sd=0
model=nfet_03v3
spiceprefix=X
}
C {devices/lab_wire.sym} 1660 240 0 0 {name=p42 sig_type=std_logic lab=VG}
C {symbols/nfet_03v3.sym} 1710 100 0 0 {name=M85
L=2u
W=2u
nf=1
m=1
ad="'int((nf+1)/2) * W/nf * 0.18u'"
pd="'2*int((nf+1)/2) * (W/nf + 0.18u)'"
as="'int((nf+2)/2) * W/nf * 0.18u'"
ps="'2*int((nf+2)/2) * (W/nf + 0.18u)'"
nrd="'0.18u / W'" nrs="'0.18u / W'"
sa=0 sb=0 sd=0
model=nfet_03v3
spiceprefix=X
}
C {symbols/nfet_03v3.sym} 1710 190 0 0 {name=M86
L=2u
W=2u
nf=1
m=1
ad="'int((nf+1)/2) * W/nf * 0.18u'"
pd="'2*int((nf+1)/2) * (W/nf + 0.18u)'"
as="'int((nf+2)/2) * W/nf * 0.18u'"
ps="'2*int((nf+2)/2) * (W/nf + 0.18u)'"
nrd="'0.18u / W'" nrs="'0.18u / W'"
sa=0 sb=0 sd=0
model=nfet_03v3
spiceprefix=X
}
C {symbols/nfet_03v3.sym} 1710 280 0 0 {name=M87
L=2u
W=2u
nf=1
m=1
ad="'int((nf+1)/2) * W/nf * 0.18u'"
pd="'2*int((nf+1)/2) * (W/nf + 0.18u)'"
as="'int((nf+2)/2) * W/nf * 0.18u'"
ps="'2*int((nf+2)/2) * (W/nf + 0.18u)'"
nrd="'0.18u / W'" nrs="'0.18u / W'"
sa=0 sb=0 sd=0
model=nfet_03v3
spiceprefix=X
}
C {symbols/nfet_03v3.sym} 1710 380 0 0 {name=M88
L=2u
W=2u
nf=1
m=1
ad="'int((nf+1)/2) * W/nf * 0.18u'"
pd="'2*int((nf+1)/2) * (W/nf + 0.18u)'"
as="'int((nf+2)/2) * W/nf * 0.18u'"
ps="'2*int((nf+2)/2) * (W/nf + 0.18u)'"
nrd="'0.18u / W'" nrs="'0.18u / W'"
sa=0 sb=0 sd=0
model=nfet_03v3
spiceprefix=X
}
C {devices/lab_wire.sym} -280 620 0 0 {name=p43 sig_type=std_logic lab=VG}
C {devices/lab_wire.sym} -60 620 0 0 {name=p44 sig_type=std_logic lab=VG}
C {devices/lab_wire.sym} 160 620 0 0 {name=p45 sig_type=std_logic lab=VG}
C {devices/lab_wire.sym} 300 620 0 0 {name=p46 sig_type=std_logic lab=VB}
C {devices/lab_wire.sym} 80 620 0 0 {name=p47 sig_type=std_logic lab=VB}
C {devices/lab_wire.sym} -140 620 0 0 {name=p48 sig_type=std_logic lab=VB}
C {devices/lab_wire.sym} -350 620 0 0 {name=p49 sig_type=std_logic lab=VB}
C {symbols/nfet_03v3.sym} -440 480 0 0 {name=M89
L=2u
W=2u
nf=1
m=1
ad="'int((nf+1)/2) * W/nf * 0.18u'"
pd="'2*int((nf+1)/2) * (W/nf + 0.18u)'"
as="'int((nf+2)/2) * W/nf * 0.18u'"
ps="'2*int((nf+2)/2) * (W/nf + 0.18u)'"
nrd="'0.18u / W'" nrs="'0.18u / W'"
sa=0 sb=0 sd=0
model=nfet_03v3
spiceprefix=X
}
C {symbols/nfet_03v3.sym} -440 570 0 0 {name=M90
L=2u
W=2u
nf=1
m=1
ad="'int((nf+1)/2) * W/nf * 0.18u'"
pd="'2*int((nf+1)/2) * (W/nf + 0.18u)'"
as="'int((nf+2)/2) * W/nf * 0.18u'"
ps="'2*int((nf+2)/2) * (W/nf + 0.18u)'"
nrd="'0.18u / W'" nrs="'0.18u / W'"
sa=0 sb=0 sd=0
model=nfet_03v3
spiceprefix=X
}
C {symbols/nfet_03v3.sym} -440 660 0 0 {name=M91
L=2u
W=2u
nf=1
m=1
ad="'int((nf+1)/2) * W/nf * 0.18u'"
pd="'2*int((nf+1)/2) * (W/nf + 0.18u)'"
as="'int((nf+2)/2) * W/nf * 0.18u'"
ps="'2*int((nf+2)/2) * (W/nf + 0.18u)'"
nrd="'0.18u / W'" nrs="'0.18u / W'"
sa=0 sb=0 sd=0
model=nfet_03v3
spiceprefix=X
}
C {symbols/nfet_03v3.sym} -230 480 0 0 {name=M92
L=2u
W=2u
nf=1
m=1
ad="'int((nf+1)/2) * W/nf * 0.18u'"
pd="'2*int((nf+1)/2) * (W/nf + 0.18u)'"
as="'int((nf+2)/2) * W/nf * 0.18u'"
ps="'2*int((nf+2)/2) * (W/nf + 0.18u)'"
nrd="'0.18u / W'" nrs="'0.18u / W'"
sa=0 sb=0 sd=0
model=nfet_03v3
spiceprefix=X
}
C {symbols/nfet_03v3.sym} -230 570 0 0 {name=M93
L=2u
W=2u
nf=1
m=1
ad="'int((nf+1)/2) * W/nf * 0.18u'"
pd="'2*int((nf+1)/2) * (W/nf + 0.18u)'"
as="'int((nf+2)/2) * W/nf * 0.18u'"
ps="'2*int((nf+2)/2) * (W/nf + 0.18u)'"
nrd="'0.18u / W'" nrs="'0.18u / W'"
sa=0 sb=0 sd=0
model=nfet_03v3
spiceprefix=X
}
C {symbols/nfet_03v3.sym} -230 660 0 0 {name=M94
L=2u
W=2u
nf=1
m=1
ad="'int((nf+1)/2) * W/nf * 0.18u'"
pd="'2*int((nf+1)/2) * (W/nf + 0.18u)'"
as="'int((nf+2)/2) * W/nf * 0.18u'"
ps="'2*int((nf+2)/2) * (W/nf + 0.18u)'"
nrd="'0.18u / W'" nrs="'0.18u / W'"
sa=0 sb=0 sd=0
model=nfet_03v3
spiceprefix=X
}
C {symbols/nfet_03v3.sym} -10 480 0 0 {name=M95
L=2u
W=2u
nf=1
m=1
ad="'int((nf+1)/2) * W/nf * 0.18u'"
pd="'2*int((nf+1)/2) * (W/nf + 0.18u)'"
as="'int((nf+2)/2) * W/nf * 0.18u'"
ps="'2*int((nf+2)/2) * (W/nf + 0.18u)'"
nrd="'0.18u / W'" nrs="'0.18u / W'"
sa=0 sb=0 sd=0
model=nfet_03v3
spiceprefix=X
}
C {symbols/nfet_03v3.sym} -10 570 0 0 {name=M96
L=2u
W=2u
nf=1
m=1
ad="'int((nf+1)/2) * W/nf * 0.18u'"
pd="'2*int((nf+1)/2) * (W/nf + 0.18u)'"
as="'int((nf+2)/2) * W/nf * 0.18u'"
ps="'2*int((nf+2)/2) * (W/nf + 0.18u)'"
nrd="'0.18u / W'" nrs="'0.18u / W'"
sa=0 sb=0 sd=0
model=nfet_03v3
spiceprefix=X
}
C {symbols/nfet_03v3.sym} -10 660 0 0 {name=M97
L=2u
W=2u
nf=1
m=1
ad="'int((nf+1)/2) * W/nf * 0.18u'"
pd="'2*int((nf+1)/2) * (W/nf + 0.18u)'"
as="'int((nf+2)/2) * W/nf * 0.18u'"
ps="'2*int((nf+2)/2) * (W/nf + 0.18u)'"
nrd="'0.18u / W'" nrs="'0.18u / W'"
sa=0 sb=0 sd=0
model=nfet_03v3
spiceprefix=X
}
C {symbols/nfet_03v3.sym} 210 480 0 0 {name=M98
L=2u
W=2u
nf=1
m=1
ad="'int((nf+1)/2) * W/nf * 0.18u'"
pd="'2*int((nf+1)/2) * (W/nf + 0.18u)'"
as="'int((nf+2)/2) * W/nf * 0.18u'"
ps="'2*int((nf+2)/2) * (W/nf + 0.18u)'"
nrd="'0.18u / W'" nrs="'0.18u / W'"
sa=0 sb=0 sd=0
model=nfet_03v3
spiceprefix=X
}
C {symbols/nfet_03v3.sym} 210 570 0 0 {name=M99
L=2u
W=2u
nf=1
m=1
ad="'int((nf+1)/2) * W/nf * 0.18u'"
pd="'2*int((nf+1)/2) * (W/nf + 0.18u)'"
as="'int((nf+2)/2) * W/nf * 0.18u'"
ps="'2*int((nf+2)/2) * (W/nf + 0.18u)'"
nrd="'0.18u / W'" nrs="'0.18u / W'"
sa=0 sb=0 sd=0
model=nfet_03v3
spiceprefix=X
}
C {symbols/nfet_03v3.sym} 210 660 0 0 {name=M100
L=2u
W=2u
nf=1
m=1
ad="'int((nf+1)/2) * W/nf * 0.18u'"
pd="'2*int((nf+1)/2) * (W/nf + 0.18u)'"
as="'int((nf+2)/2) * W/nf * 0.18u'"
ps="'2*int((nf+2)/2) * (W/nf + 0.18u)'"
nrd="'0.18u / W'" nrs="'0.18u / W'"
sa=0 sb=0 sd=0
model=nfet_03v3
spiceprefix=X
}
C {devices/lab_wire.sym} 380 620 0 0 {name=p50 sig_type=std_logic lab=VG}
C {devices/lab_wire.sym} 520 620 0 0 {name=p51 sig_type=std_logic lab=VB}
C {symbols/nfet_03v3.sym} 430 480 0 0 {name=M101
L=2u
W=2u
nf=1
m=1
ad="'int((nf+1)/2) * W/nf * 0.18u'"
pd="'2*int((nf+1)/2) * (W/nf + 0.18u)'"
as="'int((nf+2)/2) * W/nf * 0.18u'"
ps="'2*int((nf+2)/2) * (W/nf + 0.18u)'"
nrd="'0.18u / W'" nrs="'0.18u / W'"
sa=0 sb=0 sd=0
model=nfet_03v3
spiceprefix=X
}
C {symbols/nfet_03v3.sym} 430 570 0 0 {name=M102
L=2u
W=2u
nf=1
m=1
ad="'int((nf+1)/2) * W/nf * 0.18u'"
pd="'2*int((nf+1)/2) * (W/nf + 0.18u)'"
as="'int((nf+2)/2) * W/nf * 0.18u'"
ps="'2*int((nf+2)/2) * (W/nf + 0.18u)'"
nrd="'0.18u / W'" nrs="'0.18u / W'"
sa=0 sb=0 sd=0
model=nfet_03v3
spiceprefix=X
}
C {symbols/nfet_03v3.sym} 430 660 0 0 {name=M103
L=2u
W=2u
nf=1
m=1
ad="'int((nf+1)/2) * W/nf * 0.18u'"
pd="'2*int((nf+1)/2) * (W/nf + 0.18u)'"
as="'int((nf+2)/2) * W/nf * 0.18u'"
ps="'2*int((nf+2)/2) * (W/nf + 0.18u)'"
nrd="'0.18u / W'" nrs="'0.18u / W'"
sa=0 sb=0 sd=0
model=nfet_03v3
spiceprefix=X
}
C {symbols/nfet_03v3.sym} -440 760 0 0 {name=M104
L=2u
W=2u
nf=1
m=1
ad="'int((nf+1)/2) * W/nf * 0.18u'"
pd="'2*int((nf+1)/2) * (W/nf + 0.18u)'"
as="'int((nf+2)/2) * W/nf * 0.18u'"
ps="'2*int((nf+2)/2) * (W/nf + 0.18u)'"
nrd="'0.18u / W'" nrs="'0.18u / W'"
sa=0 sb=0 sd=0
model=nfet_03v3
spiceprefix=X
}
C {symbols/nfet_03v3.sym} -230 760 0 0 {name=M105
L=2u
W=2u
nf=1
m=1
ad="'int((nf+1)/2) * W/nf * 0.18u'"
pd="'2*int((nf+1)/2) * (W/nf + 0.18u)'"
as="'int((nf+2)/2) * W/nf * 0.18u'"
ps="'2*int((nf+2)/2) * (W/nf + 0.18u)'"
nrd="'0.18u / W'" nrs="'0.18u / W'"
sa=0 sb=0 sd=0
model=nfet_03v3
spiceprefix=X
}
C {symbols/nfet_03v3.sym} -10 760 0 0 {name=M106
L=2u
W=2u
nf=1
m=1
ad="'int((nf+1)/2) * W/nf * 0.18u'"
pd="'2*int((nf+1)/2) * (W/nf + 0.18u)'"
as="'int((nf+2)/2) * W/nf * 0.18u'"
ps="'2*int((nf+2)/2) * (W/nf + 0.18u)'"
nrd="'0.18u / W'" nrs="'0.18u / W'"
sa=0 sb=0 sd=0
model=nfet_03v3
spiceprefix=X
}
C {symbols/nfet_03v3.sym} 210 760 0 0 {name=M107
L=2u
W=2u
nf=1
m=1
ad="'int((nf+1)/2) * W/nf * 0.18u'"
pd="'2*int((nf+1)/2) * (W/nf + 0.18u)'"
as="'int((nf+2)/2) * W/nf * 0.18u'"
ps="'2*int((nf+2)/2) * (W/nf + 0.18u)'"
nrd="'0.18u / W'" nrs="'0.18u / W'"
sa=0 sb=0 sd=0
model=nfet_03v3
spiceprefix=X
}
C {symbols/nfet_03v3.sym} 430 760 0 0 {name=M108
L=2u
W=2u
nf=1
m=1
ad="'int((nf+1)/2) * W/nf * 0.18u'"
pd="'2*int((nf+1)/2) * (W/nf + 0.18u)'"
as="'int((nf+2)/2) * W/nf * 0.18u'"
ps="'2*int((nf+2)/2) * (W/nf + 0.18u)'"
nrd="'0.18u / W'" nrs="'0.18u / W'"
sa=0 sb=0 sd=0
model=nfet_03v3
spiceprefix=X
}
C {devices/lab_wire.sym} 800 620 0 0 {name=p52 sig_type=std_logic lab=VG}
C {devices/lab_wire.sym} 1020 620 0 0 {name=p53 sig_type=std_logic lab=VG}
C {devices/lab_wire.sym} 1240 620 0 0 {name=p54 sig_type=std_logic lab=VG}
C {devices/lab_wire.sym} 1380 620 0 0 {name=p55 sig_type=std_logic lab=VB}
C {devices/lab_wire.sym} 1160 620 0 0 {name=p56 sig_type=std_logic lab=VB}
C {devices/lab_wire.sym} 940 620 0 0 {name=p57 sig_type=std_logic lab=VB}
C {devices/lab_wire.sym} 730 620 0 0 {name=p58 sig_type=std_logic lab=VB}
C {symbols/nfet_03v3.sym} 640 480 0 0 {name=M109
L=2u
W=2u
nf=1
m=1
ad="'int((nf+1)/2) * W/nf * 0.18u'"
pd="'2*int((nf+1)/2) * (W/nf + 0.18u)'"
as="'int((nf+2)/2) * W/nf * 0.18u'"
ps="'2*int((nf+2)/2) * (W/nf + 0.18u)'"
nrd="'0.18u / W'" nrs="'0.18u / W'"
sa=0 sb=0 sd=0
model=nfet_03v3
spiceprefix=X
}
C {symbols/nfet_03v3.sym} 640 570 0 0 {name=M110
L=2u
W=2u
nf=1
m=1
ad="'int((nf+1)/2) * W/nf * 0.18u'"
pd="'2*int((nf+1)/2) * (W/nf + 0.18u)'"
as="'int((nf+2)/2) * W/nf * 0.18u'"
ps="'2*int((nf+2)/2) * (W/nf + 0.18u)'"
nrd="'0.18u / W'" nrs="'0.18u / W'"
sa=0 sb=0 sd=0
model=nfet_03v3
spiceprefix=X
}
C {symbols/nfet_03v3.sym} 640 660 0 0 {name=M111
L=2u
W=2u
nf=1
m=1
ad="'int((nf+1)/2) * W/nf * 0.18u'"
pd="'2*int((nf+1)/2) * (W/nf + 0.18u)'"
as="'int((nf+2)/2) * W/nf * 0.18u'"
ps="'2*int((nf+2)/2) * (W/nf + 0.18u)'"
nrd="'0.18u / W'" nrs="'0.18u / W'"
sa=0 sb=0 sd=0
model=nfet_03v3
spiceprefix=X
}
C {symbols/nfet_03v3.sym} 850 480 0 0 {name=M112
L=2u
W=2u
nf=1
m=1
ad="'int((nf+1)/2) * W/nf * 0.18u'"
pd="'2*int((nf+1)/2) * (W/nf + 0.18u)'"
as="'int((nf+2)/2) * W/nf * 0.18u'"
ps="'2*int((nf+2)/2) * (W/nf + 0.18u)'"
nrd="'0.18u / W'" nrs="'0.18u / W'"
sa=0 sb=0 sd=0
model=nfet_03v3
spiceprefix=X
}
C {symbols/nfet_03v3.sym} 850 570 0 0 {name=M113
L=2u
W=2u
nf=1
m=1
ad="'int((nf+1)/2) * W/nf * 0.18u'"
pd="'2*int((nf+1)/2) * (W/nf + 0.18u)'"
as="'int((nf+2)/2) * W/nf * 0.18u'"
ps="'2*int((nf+2)/2) * (W/nf + 0.18u)'"
nrd="'0.18u / W'" nrs="'0.18u / W'"
sa=0 sb=0 sd=0
model=nfet_03v3
spiceprefix=X
}
C {symbols/nfet_03v3.sym} 850 660 0 0 {name=M114
L=2u
W=2u
nf=1
m=1
ad="'int((nf+1)/2) * W/nf * 0.18u'"
pd="'2*int((nf+1)/2) * (W/nf + 0.18u)'"
as="'int((nf+2)/2) * W/nf * 0.18u'"
ps="'2*int((nf+2)/2) * (W/nf + 0.18u)'"
nrd="'0.18u / W'" nrs="'0.18u / W'"
sa=0 sb=0 sd=0
model=nfet_03v3
spiceprefix=X
}
C {symbols/nfet_03v3.sym} 1070 480 0 0 {name=M115
L=2u
W=2u
nf=1
m=1
ad="'int((nf+1)/2) * W/nf * 0.18u'"
pd="'2*int((nf+1)/2) * (W/nf + 0.18u)'"
as="'int((nf+2)/2) * W/nf * 0.18u'"
ps="'2*int((nf+2)/2) * (W/nf + 0.18u)'"
nrd="'0.18u / W'" nrs="'0.18u / W'"
sa=0 sb=0 sd=0
model=nfet_03v3
spiceprefix=X
}
C {symbols/nfet_03v3.sym} 1070 570 0 0 {name=M116
L=2u
W=2u
nf=1
m=1
ad="'int((nf+1)/2) * W/nf * 0.18u'"
pd="'2*int((nf+1)/2) * (W/nf + 0.18u)'"
as="'int((nf+2)/2) * W/nf * 0.18u'"
ps="'2*int((nf+2)/2) * (W/nf + 0.18u)'"
nrd="'0.18u / W'" nrs="'0.18u / W'"
sa=0 sb=0 sd=0
model=nfet_03v3
spiceprefix=X
}
C {symbols/nfet_03v3.sym} 1070 660 0 0 {name=M117
L=2u
W=2u
nf=1
m=1
ad="'int((nf+1)/2) * W/nf * 0.18u'"
pd="'2*int((nf+1)/2) * (W/nf + 0.18u)'"
as="'int((nf+2)/2) * W/nf * 0.18u'"
ps="'2*int((nf+2)/2) * (W/nf + 0.18u)'"
nrd="'0.18u / W'" nrs="'0.18u / W'"
sa=0 sb=0 sd=0
model=nfet_03v3
spiceprefix=X
}
C {symbols/nfet_03v3.sym} 1290 480 0 0 {name=M118
L=2u
W=2u
nf=1
m=1
ad="'int((nf+1)/2) * W/nf * 0.18u'"
pd="'2*int((nf+1)/2) * (W/nf + 0.18u)'"
as="'int((nf+2)/2) * W/nf * 0.18u'"
ps="'2*int((nf+2)/2) * (W/nf + 0.18u)'"
nrd="'0.18u / W'" nrs="'0.18u / W'"
sa=0 sb=0 sd=0
model=nfet_03v3
spiceprefix=X
}
C {symbols/nfet_03v3.sym} 1290 570 0 0 {name=M119
L=2u
W=2u
nf=1
m=1
ad="'int((nf+1)/2) * W/nf * 0.18u'"
pd="'2*int((nf+1)/2) * (W/nf + 0.18u)'"
as="'int((nf+2)/2) * W/nf * 0.18u'"
ps="'2*int((nf+2)/2) * (W/nf + 0.18u)'"
nrd="'0.18u / W'" nrs="'0.18u / W'"
sa=0 sb=0 sd=0
model=nfet_03v3
spiceprefix=X
}
C {symbols/nfet_03v3.sym} 1290 660 0 0 {name=M120
L=2u
W=2u
nf=1
m=1
ad="'int((nf+1)/2) * W/nf * 0.18u'"
pd="'2*int((nf+1)/2) * (W/nf + 0.18u)'"
as="'int((nf+2)/2) * W/nf * 0.18u'"
ps="'2*int((nf+2)/2) * (W/nf + 0.18u)'"
nrd="'0.18u / W'" nrs="'0.18u / W'"
sa=0 sb=0 sd=0
model=nfet_03v3
spiceprefix=X
}
C {devices/lab_wire.sym} 1460 620 0 0 {name=p59 sig_type=std_logic lab=VG}
C {devices/lab_wire.sym} 1600 620 0 0 {name=p60 sig_type=std_logic lab=VB}
C {symbols/nfet_03v3.sym} 1510 480 0 0 {name=M121
L=2u
W=2u
nf=1
m=1
ad="'int((nf+1)/2) * W/nf * 0.18u'"
pd="'2*int((nf+1)/2) * (W/nf + 0.18u)'"
as="'int((nf+2)/2) * W/nf * 0.18u'"
ps="'2*int((nf+2)/2) * (W/nf + 0.18u)'"
nrd="'0.18u / W'" nrs="'0.18u / W'"
sa=0 sb=0 sd=0
model=nfet_03v3
spiceprefix=X
}
C {symbols/nfet_03v3.sym} 1510 570 0 0 {name=M122
L=2u
W=2u
nf=1
m=1
ad="'int((nf+1)/2) * W/nf * 0.18u'"
pd="'2*int((nf+1)/2) * (W/nf + 0.18u)'"
as="'int((nf+2)/2) * W/nf * 0.18u'"
ps="'2*int((nf+2)/2) * (W/nf + 0.18u)'"
nrd="'0.18u / W'" nrs="'0.18u / W'"
sa=0 sb=0 sd=0
model=nfet_03v3
spiceprefix=X
}
C {symbols/nfet_03v3.sym} 1510 660 0 0 {name=M123
L=2u
W=2u
nf=1
m=1
ad="'int((nf+1)/2) * W/nf * 0.18u'"
pd="'2*int((nf+1)/2) * (W/nf + 0.18u)'"
as="'int((nf+2)/2) * W/nf * 0.18u'"
ps="'2*int((nf+2)/2) * (W/nf + 0.18u)'"
nrd="'0.18u / W'" nrs="'0.18u / W'"
sa=0 sb=0 sd=0
model=nfet_03v3
spiceprefix=X
}
C {symbols/nfet_03v3.sym} 640 760 0 0 {name=M124
L=2u
W=2u
nf=1
m=1
ad="'int((nf+1)/2) * W/nf * 0.18u'"
pd="'2*int((nf+1)/2) * (W/nf + 0.18u)'"
as="'int((nf+2)/2) * W/nf * 0.18u'"
ps="'2*int((nf+2)/2) * (W/nf + 0.18u)'"
nrd="'0.18u / W'" nrs="'0.18u / W'"
sa=0 sb=0 sd=0
model=nfet_03v3
spiceprefix=X
}
C {symbols/nfet_03v3.sym} 850 760 0 0 {name=M125
L=2u
W=2u
nf=1
m=1
ad="'int((nf+1)/2) * W/nf * 0.18u'"
pd="'2*int((nf+1)/2) * (W/nf + 0.18u)'"
as="'int((nf+2)/2) * W/nf * 0.18u'"
ps="'2*int((nf+2)/2) * (W/nf + 0.18u)'"
nrd="'0.18u / W'" nrs="'0.18u / W'"
sa=0 sb=0 sd=0
model=nfet_03v3
spiceprefix=X
}
C {symbols/nfet_03v3.sym} 1070 760 0 0 {name=M126
L=2u
W=2u
nf=1
m=1
ad="'int((nf+1)/2) * W/nf * 0.18u'"
pd="'2*int((nf+1)/2) * (W/nf + 0.18u)'"
as="'int((nf+2)/2) * W/nf * 0.18u'"
ps="'2*int((nf+2)/2) * (W/nf + 0.18u)'"
nrd="'0.18u / W'" nrs="'0.18u / W'"
sa=0 sb=0 sd=0
model=nfet_03v3
spiceprefix=X
}
C {symbols/nfet_03v3.sym} 1290 760 0 0 {name=M127
L=2u
W=2u
nf=1
m=1
ad="'int((nf+1)/2) * W/nf * 0.18u'"
pd="'2*int((nf+1)/2) * (W/nf + 0.18u)'"
as="'int((nf+2)/2) * W/nf * 0.18u'"
ps="'2*int((nf+2)/2) * (W/nf + 0.18u)'"
nrd="'0.18u / W'" nrs="'0.18u / W'"
sa=0 sb=0 sd=0
model=nfet_03v3
spiceprefix=X
}
C {symbols/nfet_03v3.sym} 1510 760 0 0 {name=M128
L=2u
W=2u
nf=1
m=1
ad="'int((nf+1)/2) * W/nf * 0.18u'"
pd="'2*int((nf+1)/2) * (W/nf + 0.18u)'"
as="'int((nf+2)/2) * W/nf * 0.18u'"
ps="'2*int((nf+2)/2) * (W/nf + 0.18u)'"
nrd="'0.18u / W'" nrs="'0.18u / W'"
sa=0 sb=0 sd=0
model=nfet_03v3
spiceprefix=X
}
C {devices/lab_wire.sym} 1660 620 0 0 {name=p61 sig_type=std_logic lab=VG}
C {symbols/nfet_03v3.sym} 1710 480 0 0 {name=M129
L=2u
W=2u
nf=1
m=1
ad="'int((nf+1)/2) * W/nf * 0.18u'"
pd="'2*int((nf+1)/2) * (W/nf + 0.18u)'"
as="'int((nf+2)/2) * W/nf * 0.18u'"
ps="'2*int((nf+2)/2) * (W/nf + 0.18u)'"
nrd="'0.18u / W'" nrs="'0.18u / W'"
sa=0 sb=0 sd=0
model=nfet_03v3
spiceprefix=X
}
C {symbols/nfet_03v3.sym} 1710 570 0 0 {name=M130
L=2u
W=2u
nf=1
m=1
ad="'int((nf+1)/2) * W/nf * 0.18u'"
pd="'2*int((nf+1)/2) * (W/nf + 0.18u)'"
as="'int((nf+2)/2) * W/nf * 0.18u'"
ps="'2*int((nf+2)/2) * (W/nf + 0.18u)'"
nrd="'0.18u / W'" nrs="'0.18u / W'"
sa=0 sb=0 sd=0
model=nfet_03v3
spiceprefix=X
}
C {symbols/nfet_03v3.sym} 1710 660 0 0 {name=M131
L=2u
W=2u
nf=1
m=1
ad="'int((nf+1)/2) * W/nf * 0.18u'"
pd="'2*int((nf+1)/2) * (W/nf + 0.18u)'"
as="'int((nf+2)/2) * W/nf * 0.18u'"
ps="'2*int((nf+2)/2) * (W/nf + 0.18u)'"
nrd="'0.18u / W'" nrs="'0.18u / W'"
sa=0 sb=0 sd=0
model=nfet_03v3
spiceprefix=X
}
C {symbols/nfet_03v3.sym} 1710 760 0 0 {name=M132
L=2u
W=2u
nf=1
m=1
ad="'int((nf+1)/2) * W/nf * 0.18u'"
pd="'2*int((nf+1)/2) * (W/nf + 0.18u)'"
as="'int((nf+2)/2) * W/nf * 0.18u'"
ps="'2*int((nf+2)/2) * (W/nf + 0.18u)'"
nrd="'0.18u / W'" nrs="'0.18u / W'"
sa=0 sb=0 sd=0
model=nfet_03v3
spiceprefix=X
}
C {devices/lab_wire.sym} 600 50 0 0 {name=p62 sig_type=std_logic lab=VG}
